VERSION 5.8 ;
BUSBITCHARS "[]" ;
DIVIDERCHAR "/" ;
UNITS
    DATABASE MICRONS 1000 ;
END UNITS

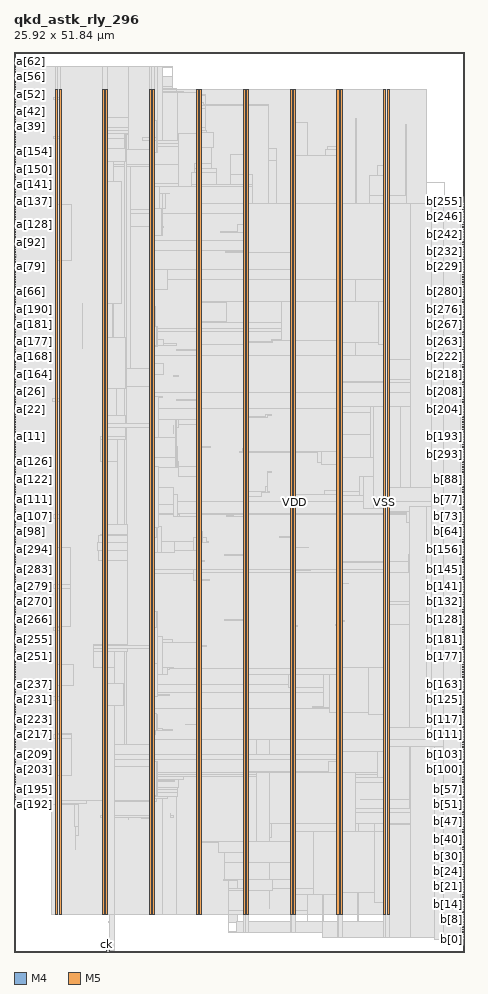
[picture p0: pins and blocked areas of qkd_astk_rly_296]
MACRO qkd_astk_rly_296
  FOREIGN qkd_astk_rly_296 0 0 ;
  CLASS BLOCK ;
  SIZE 25.92 BY 51.84 ;
  PIN a[0]
    DIRECTION INPUT ;
    USE SIGNAL ;
    PORT
      LAYER M4 ;
        RECT  0 28.08 0.084 28.104 ;
    END
  END a[0]
  PIN a[100]
    DIRECTION INPUT ;
    USE SIGNAL ;
    PORT
      LAYER M4 ;
        RECT  0 24.048 0.084 24.072 ;
    END
  END a[100]
  PIN a[101]
    DIRECTION INPUT ;
    USE SIGNAL ;
    PORT
      LAYER M4 ;
        RECT  0 24.192 0.084 24.216 ;
    END
  END a[101]
  PIN a[102]
    DIRECTION INPUT ;
    USE SIGNAL ;
    PORT
      LAYER M4 ;
        RECT  0 24.336 0.084 24.36 ;
    END
  END a[102]
  PIN a[103]
    DIRECTION INPUT ;
    USE SIGNAL ;
    PORT
      LAYER M4 ;
        RECT  0 24.48 0.084 24.504 ;
    END
  END a[103]
  PIN a[104]
    DIRECTION INPUT ;
    USE SIGNAL ;
    PORT
      LAYER M4 ;
        RECT  0 24.624 0.084 24.648 ;
    END
  END a[104]
  PIN a[105]
    DIRECTION INPUT ;
    USE SIGNAL ;
    PORT
      LAYER M4 ;
        RECT  0 24.768 0.084 24.792 ;
    END
  END a[105]
  PIN a[106]
    DIRECTION INPUT ;
    USE SIGNAL ;
    PORT
      LAYER M4 ;
        RECT  0 24.912 0.084 24.936 ;
    END
  END a[106]
  PIN a[107]
    DIRECTION INPUT ;
    USE SIGNAL ;
    PORT
      LAYER M4 ;
        RECT  0 25.056 0.084 25.08 ;
    END
  END a[107]
  PIN a[108]
    DIRECTION INPUT ;
    USE SIGNAL ;
    PORT
      LAYER M4 ;
        RECT  0 25.2 0.084 25.224 ;
    END
  END a[108]
  PIN a[109]
    DIRECTION INPUT ;
    USE SIGNAL ;
    PORT
      LAYER M4 ;
        RECT  0 25.344 0.084 25.368 ;
    END
  END a[109]
  PIN a[10]
    DIRECTION INPUT ;
    USE SIGNAL ;
    PORT
      LAYER M4 ;
        RECT  0 29.52 0.084 29.544 ;
    END
  END a[10]
  PIN a[110]
    DIRECTION INPUT ;
    USE SIGNAL ;
    PORT
      LAYER M4 ;
        RECT  0 25.488 0.084 25.512 ;
    END
  END a[110]
  PIN a[111]
    DIRECTION INPUT ;
    USE SIGNAL ;
    PORT
      LAYER M4 ;
        RECT  0 25.632 0.084 25.656 ;
    END
  END a[111]
  PIN a[112]
    DIRECTION INPUT ;
    USE SIGNAL ;
    PORT
      LAYER M4 ;
        RECT  0 25.776 0.084 25.8 ;
    END
  END a[112]
  PIN a[113]
    DIRECTION INPUT ;
    USE SIGNAL ;
    PORT
      LAYER M4 ;
        RECT  0 25.92 0.084 25.944 ;
    END
  END a[113]
  PIN a[114]
    DIRECTION INPUT ;
    USE SIGNAL ;
    PORT
      LAYER M4 ;
        RECT  0 26.064 0.084 26.088 ;
    END
  END a[114]
  PIN a[115]
    DIRECTION INPUT ;
    USE SIGNAL ;
    PORT
      LAYER M4 ;
        RECT  0 26.208 0.084 26.232 ;
    END
  END a[115]
  PIN a[116]
    DIRECTION INPUT ;
    USE SIGNAL ;
    PORT
      LAYER M4 ;
        RECT  0 26.352 0.084 26.376 ;
    END
  END a[116]
  PIN a[117]
    DIRECTION INPUT ;
    USE SIGNAL ;
    PORT
      LAYER M4 ;
        RECT  0 26.496 0.084 26.52 ;
    END
  END a[117]
  PIN a[118]
    DIRECTION INPUT ;
    USE SIGNAL ;
    PORT
      LAYER M4 ;
        RECT  0 26.64 0.084 26.664 ;
    END
  END a[118]
  PIN a[119]
    DIRECTION INPUT ;
    USE SIGNAL ;
    PORT
      LAYER M4 ;
        RECT  0 26.784 0.084 26.808 ;
    END
  END a[119]
  PIN a[11]
    DIRECTION INPUT ;
    USE SIGNAL ;
    PORT
      LAYER M4 ;
        RECT  0 29.664 0.084 29.688 ;
    END
  END a[11]
  PIN a[120]
    DIRECTION INPUT ;
    USE SIGNAL ;
    PORT
      LAYER M4 ;
        RECT  0 26.928 0.084 26.952 ;
    END
  END a[120]
  PIN a[121]
    DIRECTION INPUT ;
    USE SIGNAL ;
    PORT
      LAYER M4 ;
        RECT  0 27.072 0.084 27.096 ;
    END
  END a[121]
  PIN a[122]
    DIRECTION INPUT ;
    USE SIGNAL ;
    PORT
      LAYER M4 ;
        RECT  0 27.216 0.084 27.24 ;
    END
  END a[122]
  PIN a[123]
    DIRECTION INPUT ;
    USE SIGNAL ;
    PORT
      LAYER M4 ;
        RECT  0 27.36 0.084 27.384 ;
    END
  END a[123]
  PIN a[124]
    DIRECTION INPUT ;
    USE SIGNAL ;
    PORT
      LAYER M4 ;
        RECT  0 27.504 0.084 27.528 ;
    END
  END a[124]
  PIN a[125]
    DIRECTION INPUT ;
    USE SIGNAL ;
    PORT
      LAYER M4 ;
        RECT  0 27.648 0.084 27.672 ;
    END
  END a[125]
  PIN a[126]
    DIRECTION INPUT ;
    USE SIGNAL ;
    PORT
      LAYER M4 ;
        RECT  0 27.792 0.084 27.816 ;
    END
  END a[126]
  PIN a[127]
    DIRECTION INPUT ;
    USE SIGNAL ;
    PORT
      LAYER M4 ;
        RECT  0 27.936 0.084 27.96 ;
    END
  END a[127]
  PIN a[128]
    DIRECTION INPUT ;
    USE SIGNAL ;
    PORT
      LAYER M4 ;
        RECT  0 41.904 0.084 41.928 ;
    END
  END a[128]
  PIN a[129]
    DIRECTION INPUT ;
    USE SIGNAL ;
    PORT
      LAYER M4 ;
        RECT  0 42.048 0.084 42.072 ;
    END
  END a[129]
  PIN a[12]
    DIRECTION INPUT ;
    USE SIGNAL ;
    PORT
      LAYER M4 ;
        RECT  0 29.808 0.084 29.832 ;
    END
  END a[12]
  PIN a[130]
    DIRECTION INPUT ;
    USE SIGNAL ;
    PORT
      LAYER M4 ;
        RECT  0 42.192 0.084 42.216 ;
    END
  END a[130]
  PIN a[131]
    DIRECTION INPUT ;
    USE SIGNAL ;
    PORT
      LAYER M4 ;
        RECT  0 42.336 0.084 42.36 ;
    END
  END a[131]
  PIN a[132]
    DIRECTION INPUT ;
    USE SIGNAL ;
    PORT
      LAYER M4 ;
        RECT  0 42.48 0.084 42.504 ;
    END
  END a[132]
  PIN a[133]
    DIRECTION INPUT ;
    USE SIGNAL ;
    PORT
      LAYER M4 ;
        RECT  0 42.624 0.084 42.648 ;
    END
  END a[133]
  PIN a[134]
    DIRECTION INPUT ;
    USE SIGNAL ;
    PORT
      LAYER M4 ;
        RECT  0 42.768 0.084 42.792 ;
    END
  END a[134]
  PIN a[135]
    DIRECTION INPUT ;
    USE SIGNAL ;
    PORT
      LAYER M4 ;
        RECT  0 42.912 0.084 42.936 ;
    END
  END a[135]
  PIN a[136]
    DIRECTION INPUT ;
    USE SIGNAL ;
    PORT
      LAYER M4 ;
        RECT  0 43.056 0.084 43.08 ;
    END
  END a[136]
  PIN a[137]
    DIRECTION INPUT ;
    USE SIGNAL ;
    PORT
      LAYER M4 ;
        RECT  0 43.2 0.084 43.224 ;
    END
  END a[137]
  PIN a[138]
    DIRECTION INPUT ;
    USE SIGNAL ;
    PORT
      LAYER M4 ;
        RECT  0 43.344 0.084 43.368 ;
    END
  END a[138]
  PIN a[139]
    DIRECTION INPUT ;
    USE SIGNAL ;
    PORT
      LAYER M4 ;
        RECT  0 43.488 0.084 43.512 ;
    END
  END a[139]
  PIN a[13]
    DIRECTION INPUT ;
    USE SIGNAL ;
    PORT
      LAYER M4 ;
        RECT  0 29.952 0.084 29.976 ;
    END
  END a[13]
  PIN a[140]
    DIRECTION INPUT ;
    USE SIGNAL ;
    PORT
      LAYER M4 ;
        RECT  0 43.632 0.084 43.656 ;
    END
  END a[140]
  PIN a[141]
    DIRECTION INPUT ;
    USE SIGNAL ;
    PORT
      LAYER M4 ;
        RECT  0 43.776 0.084 43.8 ;
    END
  END a[141]
  PIN a[142]
    DIRECTION INPUT ;
    USE SIGNAL ;
    PORT
      LAYER M4 ;
        RECT  0 43.92 0.084 43.944 ;
    END
  END a[142]
  PIN a[143]
    DIRECTION INPUT ;
    USE SIGNAL ;
    PORT
      LAYER M4 ;
        RECT  0 44.064 0.084 44.088 ;
    END
  END a[143]
  PIN a[144]
    DIRECTION INPUT ;
    USE SIGNAL ;
    PORT
      LAYER M4 ;
        RECT  0 44.208 0.084 44.232 ;
    END
  END a[144]
  PIN a[145]
    DIRECTION INPUT ;
    USE SIGNAL ;
    PORT
      LAYER M4 ;
        RECT  0 44.352 0.084 44.376 ;
    END
  END a[145]
  PIN a[146]
    DIRECTION INPUT ;
    USE SIGNAL ;
    PORT
      LAYER M4 ;
        RECT  0 44.496 0.084 44.52 ;
    END
  END a[146]
  PIN a[147]
    DIRECTION INPUT ;
    USE SIGNAL ;
    PORT
      LAYER M4 ;
        RECT  0 44.64 0.084 44.664 ;
    END
  END a[147]
  PIN a[148]
    DIRECTION INPUT ;
    USE SIGNAL ;
    PORT
      LAYER M4 ;
        RECT  0 44.784 0.084 44.808 ;
    END
  END a[148]
  PIN a[149]
    DIRECTION INPUT ;
    USE SIGNAL ;
    PORT
      LAYER M4 ;
        RECT  0 44.928 0.084 44.952 ;
    END
  END a[149]
  PIN a[14]
    DIRECTION INPUT ;
    USE SIGNAL ;
    PORT
      LAYER M4 ;
        RECT  0 30.096 0.084 30.12 ;
    END
  END a[14]
  PIN a[150]
    DIRECTION INPUT ;
    USE SIGNAL ;
    PORT
      LAYER M4 ;
        RECT  0 45.072 0.084 45.096 ;
    END
  END a[150]
  PIN a[151]
    DIRECTION INPUT ;
    USE SIGNAL ;
    PORT
      LAYER M4 ;
        RECT  0 45.216 0.084 45.24 ;
    END
  END a[151]
  PIN a[152]
    DIRECTION INPUT ;
    USE SIGNAL ;
    PORT
      LAYER M4 ;
        RECT  0 45.36 0.084 45.384 ;
    END
  END a[152]
  PIN a[153]
    DIRECTION INPUT ;
    USE SIGNAL ;
    PORT
      LAYER M4 ;
        RECT  0 45.504 0.084 45.528 ;
    END
  END a[153]
  PIN a[154]
    DIRECTION INPUT ;
    USE SIGNAL ;
    PORT
      LAYER M4 ;
        RECT  0 45.648 0.084 45.672 ;
    END
  END a[154]
  PIN a[155]
    DIRECTION INPUT ;
    USE SIGNAL ;
    PORT
      LAYER M4 ;
        RECT  0 45.792 0.084 45.816 ;
    END
  END a[155]
  PIN a[156]
    DIRECTION INPUT ;
    USE SIGNAL ;
    PORT
      LAYER M4 ;
        RECT  0 45.936 0.084 45.96 ;
    END
  END a[156]
  PIN a[157]
    DIRECTION INPUT ;
    USE SIGNAL ;
    PORT
      LAYER M4 ;
        RECT  0 46.08 0.084 46.104 ;
    END
  END a[157]
  PIN a[158]
    DIRECTION INPUT ;
    USE SIGNAL ;
    PORT
      LAYER M4 ;
        RECT  0 46.224 0.084 46.248 ;
    END
  END a[158]
  PIN a[159]
    DIRECTION INPUT ;
    USE SIGNAL ;
    PORT
      LAYER M4 ;
        RECT  0 46.368 0.084 46.392 ;
    END
  END a[159]
  PIN a[15]
    DIRECTION INPUT ;
    USE SIGNAL ;
    PORT
      LAYER M4 ;
        RECT  0 30.24 0.084 30.264 ;
    END
  END a[15]
  PIN a[160]
    DIRECTION INPUT ;
    USE SIGNAL ;
    PORT
      LAYER M4 ;
        RECT  0 32.688 0.084 32.712 ;
    END
  END a[160]
  PIN a[161]
    DIRECTION INPUT ;
    USE SIGNAL ;
    PORT
      LAYER M4 ;
        RECT  0 32.832 0.084 32.856 ;
    END
  END a[161]
  PIN a[162]
    DIRECTION INPUT ;
    USE SIGNAL ;
    PORT
      LAYER M4 ;
        RECT  0 32.976 0.084 33 ;
    END
  END a[162]
  PIN a[163]
    DIRECTION INPUT ;
    USE SIGNAL ;
    PORT
      LAYER M4 ;
        RECT  0 33.12 0.084 33.144 ;
    END
  END a[163]
  PIN a[164]
    DIRECTION INPUT ;
    USE SIGNAL ;
    PORT
      LAYER M4 ;
        RECT  0 33.264 0.084 33.288 ;
    END
  END a[164]
  PIN a[165]
    DIRECTION INPUT ;
    USE SIGNAL ;
    PORT
      LAYER M4 ;
        RECT  0 33.408 0.084 33.432 ;
    END
  END a[165]
  PIN a[166]
    DIRECTION INPUT ;
    USE SIGNAL ;
    PORT
      LAYER M4 ;
        RECT  0 33.552 0.084 33.576 ;
    END
  END a[166]
  PIN a[167]
    DIRECTION INPUT ;
    USE SIGNAL ;
    PORT
      LAYER M4 ;
        RECT  0 33.696 0.084 33.72 ;
    END
  END a[167]
  PIN a[168]
    DIRECTION INPUT ;
    USE SIGNAL ;
    PORT
      LAYER M4 ;
        RECT  0 33.84 0.084 33.864 ;
    END
  END a[168]
  PIN a[169]
    DIRECTION INPUT ;
    USE SIGNAL ;
    PORT
      LAYER M4 ;
        RECT  0 33.984 0.084 34.008 ;
    END
  END a[169]
  PIN a[16]
    DIRECTION INPUT ;
    USE SIGNAL ;
    PORT
      LAYER M4 ;
        RECT  0 30.384 0.084 30.408 ;
    END
  END a[16]
  PIN a[170]
    DIRECTION INPUT ;
    USE SIGNAL ;
    PORT
      LAYER M4 ;
        RECT  0 34.128 0.084 34.152 ;
    END
  END a[170]
  PIN a[171]
    DIRECTION INPUT ;
    USE SIGNAL ;
    PORT
      LAYER M4 ;
        RECT  0 34.272 0.084 34.296 ;
    END
  END a[171]
  PIN a[172]
    DIRECTION INPUT ;
    USE SIGNAL ;
    PORT
      LAYER M4 ;
        RECT  0 34.416 0.084 34.44 ;
    END
  END a[172]
  PIN a[173]
    DIRECTION INPUT ;
    USE SIGNAL ;
    PORT
      LAYER M4 ;
        RECT  0 34.56 0.084 34.584 ;
    END
  END a[173]
  PIN a[174]
    DIRECTION INPUT ;
    USE SIGNAL ;
    PORT
      LAYER M4 ;
        RECT  0 34.704 0.084 34.728 ;
    END
  END a[174]
  PIN a[175]
    DIRECTION INPUT ;
    USE SIGNAL ;
    PORT
      LAYER M4 ;
        RECT  0 34.848 0.084 34.872 ;
    END
  END a[175]
  PIN a[176]
    DIRECTION INPUT ;
    USE SIGNAL ;
    PORT
      LAYER M4 ;
        RECT  0 34.992 0.084 35.016 ;
    END
  END a[176]
  PIN a[177]
    DIRECTION INPUT ;
    USE SIGNAL ;
    PORT
      LAYER M4 ;
        RECT  0 35.136 0.084 35.16 ;
    END
  END a[177]
  PIN a[178]
    DIRECTION INPUT ;
    USE SIGNAL ;
    PORT
      LAYER M4 ;
        RECT  0 35.28 0.084 35.304 ;
    END
  END a[178]
  PIN a[179]
    DIRECTION INPUT ;
    USE SIGNAL ;
    PORT
      LAYER M4 ;
        RECT  0 35.424 0.084 35.448 ;
    END
  END a[179]
  PIN a[17]
    DIRECTION INPUT ;
    USE SIGNAL ;
    PORT
      LAYER M4 ;
        RECT  0 30.528 0.084 30.552 ;
    END
  END a[17]
  PIN a[180]
    DIRECTION INPUT ;
    USE SIGNAL ;
    PORT
      LAYER M4 ;
        RECT  0 35.568 0.084 35.592 ;
    END
  END a[180]
  PIN a[181]
    DIRECTION INPUT ;
    USE SIGNAL ;
    PORT
      LAYER M4 ;
        RECT  0 35.712 0.084 35.736 ;
    END
  END a[181]
  PIN a[182]
    DIRECTION INPUT ;
    USE SIGNAL ;
    PORT
      LAYER M4 ;
        RECT  0 35.856 0.084 35.88 ;
    END
  END a[182]
  PIN a[183]
    DIRECTION INPUT ;
    USE SIGNAL ;
    PORT
      LAYER M4 ;
        RECT  0 36 0.084 36.024 ;
    END
  END a[183]
  PIN a[184]
    DIRECTION INPUT ;
    USE SIGNAL ;
    PORT
      LAYER M4 ;
        RECT  0 36.144 0.084 36.168 ;
    END
  END a[184]
  PIN a[185]
    DIRECTION INPUT ;
    USE SIGNAL ;
    PORT
      LAYER M4 ;
        RECT  0 36.288 0.084 36.312 ;
    END
  END a[185]
  PIN a[186]
    DIRECTION INPUT ;
    USE SIGNAL ;
    PORT
      LAYER M4 ;
        RECT  0 36.432 0.084 36.456 ;
    END
  END a[186]
  PIN a[187]
    DIRECTION INPUT ;
    USE SIGNAL ;
    PORT
      LAYER M4 ;
        RECT  0 36.576 0.084 36.6 ;
    END
  END a[187]
  PIN a[188]
    DIRECTION INPUT ;
    USE SIGNAL ;
    PORT
      LAYER M4 ;
        RECT  0 36.72 0.084 36.744 ;
    END
  END a[188]
  PIN a[189]
    DIRECTION INPUT ;
    USE SIGNAL ;
    PORT
      LAYER M4 ;
        RECT  0 36.864 0.084 36.888 ;
    END
  END a[189]
  PIN a[18]
    DIRECTION INPUT ;
    USE SIGNAL ;
    PORT
      LAYER M4 ;
        RECT  0 30.672 0.084 30.696 ;
    END
  END a[18]
  PIN a[190]
    DIRECTION INPUT ;
    USE SIGNAL ;
    PORT
      LAYER M4 ;
        RECT  0 37.008 0.084 37.032 ;
    END
  END a[190]
  PIN a[191]
    DIRECTION INPUT ;
    USE SIGNAL ;
    PORT
      LAYER M4 ;
        RECT  0 37.152 0.084 37.176 ;
    END
  END a[191]
  PIN a[192]
    DIRECTION INPUT ;
    USE SIGNAL ;
    PORT
      LAYER M4 ;
        RECT  0 8.496 0.084 8.52 ;
    END
  END a[192]
  PIN a[193]
    DIRECTION INPUT ;
    USE SIGNAL ;
    PORT
      LAYER M4 ;
        RECT  0 8.64 0.084 8.664 ;
    END
  END a[193]
  PIN a[194]
    DIRECTION INPUT ;
    USE SIGNAL ;
    PORT
      LAYER M4 ;
        RECT  0 8.784 0.084 8.808 ;
    END
  END a[194]
  PIN a[195]
    DIRECTION INPUT ;
    USE SIGNAL ;
    PORT
      LAYER M4 ;
        RECT  0 8.928 0.084 8.952 ;
    END
  END a[195]
  PIN a[196]
    DIRECTION INPUT ;
    USE SIGNAL ;
    PORT
      LAYER M4 ;
        RECT  0 9.072 0.084 9.096 ;
    END
  END a[196]
  PIN a[197]
    DIRECTION INPUT ;
    USE SIGNAL ;
    PORT
      LAYER M4 ;
        RECT  0 9.216 0.084 9.24 ;
    END
  END a[197]
  PIN a[198]
    DIRECTION INPUT ;
    USE SIGNAL ;
    PORT
      LAYER M4 ;
        RECT  0 9.36 0.084 9.384 ;
    END
  END a[198]
  PIN a[199]
    DIRECTION INPUT ;
    USE SIGNAL ;
    PORT
      LAYER M4 ;
        RECT  0 9.504 0.084 9.528 ;
    END
  END a[199]
  PIN a[19]
    DIRECTION INPUT ;
    USE SIGNAL ;
    PORT
      LAYER M4 ;
        RECT  0 30.816 0.084 30.84 ;
    END
  END a[19]
  PIN a[1]
    DIRECTION INPUT ;
    USE SIGNAL ;
    PORT
      LAYER M4 ;
        RECT  0 28.224 0.084 28.248 ;
    END
  END a[1]
  PIN a[200]
    DIRECTION INPUT ;
    USE SIGNAL ;
    PORT
      LAYER M4 ;
        RECT  0 9.648 0.084 9.672 ;
    END
  END a[200]
  PIN a[201]
    DIRECTION INPUT ;
    USE SIGNAL ;
    PORT
      LAYER M4 ;
        RECT  0 9.792 0.084 9.816 ;
    END
  END a[201]
  PIN a[202]
    DIRECTION INPUT ;
    USE SIGNAL ;
    PORT
      LAYER M4 ;
        RECT  0 9.936 0.084 9.96 ;
    END
  END a[202]
  PIN a[203]
    DIRECTION INPUT ;
    USE SIGNAL ;
    PORT
      LAYER M4 ;
        RECT  0 10.08 0.084 10.104 ;
    END
  END a[203]
  PIN a[204]
    DIRECTION INPUT ;
    USE SIGNAL ;
    PORT
      LAYER M4 ;
        RECT  0 10.224 0.084 10.248 ;
    END
  END a[204]
  PIN a[205]
    DIRECTION INPUT ;
    USE SIGNAL ;
    PORT
      LAYER M4 ;
        RECT  0 10.368 0.084 10.392 ;
    END
  END a[205]
  PIN a[206]
    DIRECTION INPUT ;
    USE SIGNAL ;
    PORT
      LAYER M4 ;
        RECT  0 10.512 0.084 10.536 ;
    END
  END a[206]
  PIN a[207]
    DIRECTION INPUT ;
    USE SIGNAL ;
    PORT
      LAYER M4 ;
        RECT  0 10.656 0.084 10.68 ;
    END
  END a[207]
  PIN a[208]
    DIRECTION INPUT ;
    USE SIGNAL ;
    PORT
      LAYER M4 ;
        RECT  0 10.8 0.084 10.824 ;
    END
  END a[208]
  PIN a[209]
    DIRECTION INPUT ;
    USE SIGNAL ;
    PORT
      LAYER M4 ;
        RECT  0 10.944 0.084 10.968 ;
    END
  END a[209]
  PIN a[20]
    DIRECTION INPUT ;
    USE SIGNAL ;
    PORT
      LAYER M4 ;
        RECT  0 30.96 0.084 30.984 ;
    END
  END a[20]
  PIN a[210]
    DIRECTION INPUT ;
    USE SIGNAL ;
    PORT
      LAYER M4 ;
        RECT  0 11.088 0.084 11.112 ;
    END
  END a[210]
  PIN a[211]
    DIRECTION INPUT ;
    USE SIGNAL ;
    PORT
      LAYER M4 ;
        RECT  0 11.232 0.084 11.256 ;
    END
  END a[211]
  PIN a[212]
    DIRECTION INPUT ;
    USE SIGNAL ;
    PORT
      LAYER M4 ;
        RECT  0 11.376 0.084 11.4 ;
    END
  END a[212]
  PIN a[213]
    DIRECTION INPUT ;
    USE SIGNAL ;
    PORT
      LAYER M4 ;
        RECT  0 11.52 0.084 11.544 ;
    END
  END a[213]
  PIN a[214]
    DIRECTION INPUT ;
    USE SIGNAL ;
    PORT
      LAYER M4 ;
        RECT  0 11.664 0.084 11.688 ;
    END
  END a[214]
  PIN a[215]
    DIRECTION INPUT ;
    USE SIGNAL ;
    PORT
      LAYER M4 ;
        RECT  0 11.808 0.084 11.832 ;
    END
  END a[215]
  PIN a[216]
    DIRECTION INPUT ;
    USE SIGNAL ;
    PORT
      LAYER M4 ;
        RECT  0 11.952 0.084 11.976 ;
    END
  END a[216]
  PIN a[217]
    DIRECTION INPUT ;
    USE SIGNAL ;
    PORT
      LAYER M4 ;
        RECT  0 12.096 0.084 12.12 ;
    END
  END a[217]
  PIN a[218]
    DIRECTION INPUT ;
    USE SIGNAL ;
    PORT
      LAYER M4 ;
        RECT  0 12.24 0.084 12.264 ;
    END
  END a[218]
  PIN a[219]
    DIRECTION INPUT ;
    USE SIGNAL ;
    PORT
      LAYER M4 ;
        RECT  0 12.384 0.084 12.408 ;
    END
  END a[219]
  PIN a[21]
    DIRECTION INPUT ;
    USE SIGNAL ;
    PORT
      LAYER M4 ;
        RECT  0 31.104 0.084 31.128 ;
    END
  END a[21]
  PIN a[220]
    DIRECTION INPUT ;
    USE SIGNAL ;
    PORT
      LAYER M4 ;
        RECT  0 12.528 0.084 12.552 ;
    END
  END a[220]
  PIN a[221]
    DIRECTION INPUT ;
    USE SIGNAL ;
    PORT
      LAYER M4 ;
        RECT  0 12.672 0.084 12.696 ;
    END
  END a[221]
  PIN a[222]
    DIRECTION INPUT ;
    USE SIGNAL ;
    PORT
      LAYER M4 ;
        RECT  0 12.816 0.084 12.84 ;
    END
  END a[222]
  PIN a[223]
    DIRECTION INPUT ;
    USE SIGNAL ;
    PORT
      LAYER M4 ;
        RECT  0 12.96 0.084 12.984 ;
    END
  END a[223]
  PIN a[224]
    DIRECTION INPUT ;
    USE SIGNAL ;
    PORT
      LAYER M4 ;
        RECT  0 13.104 0.084 13.128 ;
    END
  END a[224]
  PIN a[225]
    DIRECTION INPUT ;
    USE SIGNAL ;
    PORT
      LAYER M4 ;
        RECT  0 13.248 0.084 13.272 ;
    END
  END a[225]
  PIN a[226]
    DIRECTION INPUT ;
    USE SIGNAL ;
    PORT
      LAYER M4 ;
        RECT  0 13.392 0.084 13.416 ;
    END
  END a[226]
  PIN a[227]
    DIRECTION INPUT ;
    USE SIGNAL ;
    PORT
      LAYER M4 ;
        RECT  0 13.536 0.084 13.56 ;
    END
  END a[227]
  PIN a[228]
    DIRECTION INPUT ;
    USE SIGNAL ;
    PORT
      LAYER M4 ;
        RECT  0 13.68 0.084 13.704 ;
    END
  END a[228]
  PIN a[229]
    DIRECTION INPUT ;
    USE SIGNAL ;
    PORT
      LAYER M4 ;
        RECT  0 13.824 0.084 13.848 ;
    END
  END a[229]
  PIN a[22]
    DIRECTION INPUT ;
    USE SIGNAL ;
    PORT
      LAYER M4 ;
        RECT  0 31.248 0.084 31.272 ;
    END
  END a[22]
  PIN a[230]
    DIRECTION INPUT ;
    USE SIGNAL ;
    PORT
      LAYER M4 ;
        RECT  0 13.968 0.084 13.992 ;
    END
  END a[230]
  PIN a[231]
    DIRECTION INPUT ;
    USE SIGNAL ;
    PORT
      LAYER M4 ;
        RECT  0 14.112 0.084 14.136 ;
    END
  END a[231]
  PIN a[232]
    DIRECTION INPUT ;
    USE SIGNAL ;
    PORT
      LAYER M4 ;
        RECT  0 14.256 0.084 14.28 ;
    END
  END a[232]
  PIN a[233]
    DIRECTION INPUT ;
    USE SIGNAL ;
    PORT
      LAYER M4 ;
        RECT  0 14.4 0.084 14.424 ;
    END
  END a[233]
  PIN a[234]
    DIRECTION INPUT ;
    USE SIGNAL ;
    PORT
      LAYER M4 ;
        RECT  0 14.544 0.084 14.568 ;
    END
  END a[234]
  PIN a[235]
    DIRECTION INPUT ;
    USE SIGNAL ;
    PORT
      LAYER M4 ;
        RECT  0 14.688 0.084 14.712 ;
    END
  END a[235]
  PIN a[236]
    DIRECTION INPUT ;
    USE SIGNAL ;
    PORT
      LAYER M4 ;
        RECT  0 14.832 0.084 14.856 ;
    END
  END a[236]
  PIN a[237]
    DIRECTION INPUT ;
    USE SIGNAL ;
    PORT
      LAYER M4 ;
        RECT  0 14.976 0.084 15 ;
    END
  END a[237]
  PIN a[238]
    DIRECTION INPUT ;
    USE SIGNAL ;
    PORT
      LAYER M4 ;
        RECT  0 15.12 0.084 15.144 ;
    END
  END a[238]
  PIN a[239]
    DIRECTION INPUT ;
    USE SIGNAL ;
    PORT
      LAYER M4 ;
        RECT  0 15.264 0.084 15.288 ;
    END
  END a[239]
  PIN a[23]
    DIRECTION INPUT ;
    USE SIGNAL ;
    PORT
      LAYER M4 ;
        RECT  0 31.392 0.084 31.416 ;
    END
  END a[23]
  PIN a[240]
    DIRECTION INPUT ;
    USE SIGNAL ;
    PORT
      LAYER M4 ;
        RECT  0 15.408 0.084 15.432 ;
    END
  END a[240]
  PIN a[241]
    DIRECTION INPUT ;
    USE SIGNAL ;
    PORT
      LAYER M4 ;
        RECT  0 15.552 0.084 15.576 ;
    END
  END a[241]
  PIN a[242]
    DIRECTION INPUT ;
    USE SIGNAL ;
    PORT
      LAYER M4 ;
        RECT  0 15.696 0.084 15.72 ;
    END
  END a[242]
  PIN a[243]
    DIRECTION INPUT ;
    USE SIGNAL ;
    PORT
      LAYER M4 ;
        RECT  0 15.84 0.084 15.864 ;
    END
  END a[243]
  PIN a[244]
    DIRECTION INPUT ;
    USE SIGNAL ;
    PORT
      LAYER M4 ;
        RECT  0 15.984 0.084 16.008 ;
    END
  END a[244]
  PIN a[245]
    DIRECTION INPUT ;
    USE SIGNAL ;
    PORT
      LAYER M4 ;
        RECT  0 16.128 0.084 16.152 ;
    END
  END a[245]
  PIN a[246]
    DIRECTION INPUT ;
    USE SIGNAL ;
    PORT
      LAYER M4 ;
        RECT  0 16.272 0.084 16.296 ;
    END
  END a[246]
  PIN a[247]
    DIRECTION INPUT ;
    USE SIGNAL ;
    PORT
      LAYER M4 ;
        RECT  0 16.416 0.084 16.44 ;
    END
  END a[247]
  PIN a[248]
    DIRECTION INPUT ;
    USE SIGNAL ;
    PORT
      LAYER M4 ;
        RECT  0 16.56 0.084 16.584 ;
    END
  END a[248]
  PIN a[249]
    DIRECTION INPUT ;
    USE SIGNAL ;
    PORT
      LAYER M4 ;
        RECT  0 16.704 0.084 16.728 ;
    END
  END a[249]
  PIN a[24]
    DIRECTION INPUT ;
    USE SIGNAL ;
    PORT
      LAYER M4 ;
        RECT  0 31.536 0.084 31.56 ;
    END
  END a[24]
  PIN a[250]
    DIRECTION INPUT ;
    USE SIGNAL ;
    PORT
      LAYER M4 ;
        RECT  0 16.848 0.084 16.872 ;
    END
  END a[250]
  PIN a[251]
    DIRECTION INPUT ;
    USE SIGNAL ;
    PORT
      LAYER M4 ;
        RECT  0 16.992 0.084 17.016 ;
    END
  END a[251]
  PIN a[252]
    DIRECTION INPUT ;
    USE SIGNAL ;
    PORT
      LAYER M4 ;
        RECT  0 17.136 0.084 17.16 ;
    END
  END a[252]
  PIN a[253]
    DIRECTION INPUT ;
    USE SIGNAL ;
    PORT
      LAYER M4 ;
        RECT  0 17.28 0.084 17.304 ;
    END
  END a[253]
  PIN a[254]
    DIRECTION INPUT ;
    USE SIGNAL ;
    PORT
      LAYER M4 ;
        RECT  0 17.424 0.084 17.448 ;
    END
  END a[254]
  PIN a[255]
    DIRECTION INPUT ;
    USE SIGNAL ;
    PORT
      LAYER M4 ;
        RECT  0 17.568 0.084 17.592 ;
    END
  END a[255]
  PIN a[256]
    DIRECTION INPUT ;
    USE SIGNAL ;
    PORT
      LAYER M4 ;
        RECT  0 17.712 0.084 17.736 ;
    END
  END a[256]
  PIN a[257]
    DIRECTION INPUT ;
    USE SIGNAL ;
    PORT
      LAYER M4 ;
        RECT  0 17.856 0.084 17.88 ;
    END
  END a[257]
  PIN a[258]
    DIRECTION INPUT ;
    USE SIGNAL ;
    PORT
      LAYER M4 ;
        RECT  0 18 0.084 18.024 ;
    END
  END a[258]
  PIN a[259]
    DIRECTION INPUT ;
    USE SIGNAL ;
    PORT
      LAYER M4 ;
        RECT  0 18.144 0.084 18.168 ;
    END
  END a[259]
  PIN a[25]
    DIRECTION INPUT ;
    USE SIGNAL ;
    PORT
      LAYER M4 ;
        RECT  0 31.68 0.084 31.704 ;
    END
  END a[25]
  PIN a[260]
    DIRECTION INPUT ;
    USE SIGNAL ;
    PORT
      LAYER M4 ;
        RECT  0 18.288 0.084 18.312 ;
    END
  END a[260]
  PIN a[261]
    DIRECTION INPUT ;
    USE SIGNAL ;
    PORT
      LAYER M4 ;
        RECT  0 18.432 0.084 18.456 ;
    END
  END a[261]
  PIN a[262]
    DIRECTION INPUT ;
    USE SIGNAL ;
    PORT
      LAYER M4 ;
        RECT  0 18.576 0.084 18.6 ;
    END
  END a[262]
  PIN a[263]
    DIRECTION INPUT ;
    USE SIGNAL ;
    PORT
      LAYER M4 ;
        RECT  0 18.72 0.084 18.744 ;
    END
  END a[263]
  PIN a[264]
    DIRECTION INPUT ;
    USE SIGNAL ;
    PORT
      LAYER M4 ;
        RECT  0 18.864 0.084 18.888 ;
    END
  END a[264]
  PIN a[265]
    DIRECTION INPUT ;
    USE SIGNAL ;
    PORT
      LAYER M4 ;
        RECT  0 19.008 0.084 19.032 ;
    END
  END a[265]
  PIN a[266]
    DIRECTION INPUT ;
    USE SIGNAL ;
    PORT
      LAYER M4 ;
        RECT  0 19.152 0.084 19.176 ;
    END
  END a[266]
  PIN a[267]
    DIRECTION INPUT ;
    USE SIGNAL ;
    PORT
      LAYER M4 ;
        RECT  0 19.296 0.084 19.32 ;
    END
  END a[267]
  PIN a[268]
    DIRECTION INPUT ;
    USE SIGNAL ;
    PORT
      LAYER M4 ;
        RECT  0 19.44 0.084 19.464 ;
    END
  END a[268]
  PIN a[269]
    DIRECTION INPUT ;
    USE SIGNAL ;
    PORT
      LAYER M4 ;
        RECT  0 19.584 0.084 19.608 ;
    END
  END a[269]
  PIN a[26]
    DIRECTION INPUT ;
    USE SIGNAL ;
    PORT
      LAYER M4 ;
        RECT  0 31.824 0.084 31.848 ;
    END
  END a[26]
  PIN a[270]
    DIRECTION INPUT ;
    USE SIGNAL ;
    PORT
      LAYER M4 ;
        RECT  0 19.728 0.084 19.752 ;
    END
  END a[270]
  PIN a[271]
    DIRECTION INPUT ;
    USE SIGNAL ;
    PORT
      LAYER M4 ;
        RECT  0 19.872 0.084 19.896 ;
    END
  END a[271]
  PIN a[272]
    DIRECTION INPUT ;
    USE SIGNAL ;
    PORT
      LAYER M4 ;
        RECT  0 20.016 0.084 20.04 ;
    END
  END a[272]
  PIN a[273]
    DIRECTION INPUT ;
    USE SIGNAL ;
    PORT
      LAYER M4 ;
        RECT  0 20.16 0.084 20.184 ;
    END
  END a[273]
  PIN a[274]
    DIRECTION INPUT ;
    USE SIGNAL ;
    PORT
      LAYER M4 ;
        RECT  0 20.304 0.084 20.328 ;
    END
  END a[274]
  PIN a[275]
    DIRECTION INPUT ;
    USE SIGNAL ;
    PORT
      LAYER M4 ;
        RECT  0 20.448 0.084 20.472 ;
    END
  END a[275]
  PIN a[276]
    DIRECTION INPUT ;
    USE SIGNAL ;
    PORT
      LAYER M4 ;
        RECT  0 20.592 0.084 20.616 ;
    END
  END a[276]
  PIN a[277]
    DIRECTION INPUT ;
    USE SIGNAL ;
    PORT
      LAYER M4 ;
        RECT  0 20.736 0.084 20.76 ;
    END
  END a[277]
  PIN a[278]
    DIRECTION INPUT ;
    USE SIGNAL ;
    PORT
      LAYER M4 ;
        RECT  0 20.88 0.084 20.904 ;
    END
  END a[278]
  PIN a[279]
    DIRECTION INPUT ;
    USE SIGNAL ;
    PORT
      LAYER M4 ;
        RECT  0 21.024 0.084 21.048 ;
    END
  END a[279]
  PIN a[27]
    DIRECTION INPUT ;
    USE SIGNAL ;
    PORT
      LAYER M4 ;
        RECT  0 31.968 0.084 31.992 ;
    END
  END a[27]
  PIN a[280]
    DIRECTION INPUT ;
    USE SIGNAL ;
    PORT
      LAYER M4 ;
        RECT  0 21.168 0.084 21.192 ;
    END
  END a[280]
  PIN a[281]
    DIRECTION INPUT ;
    USE SIGNAL ;
    PORT
      LAYER M4 ;
        RECT  0 21.312 0.084 21.336 ;
    END
  END a[281]
  PIN a[282]
    DIRECTION INPUT ;
    USE SIGNAL ;
    PORT
      LAYER M4 ;
        RECT  0 21.456 0.084 21.48 ;
    END
  END a[282]
  PIN a[283]
    DIRECTION INPUT ;
    USE SIGNAL ;
    PORT
      LAYER M4 ;
        RECT  0 21.6 0.084 21.624 ;
    END
  END a[283]
  PIN a[284]
    DIRECTION INPUT ;
    USE SIGNAL ;
    PORT
      LAYER M4 ;
        RECT  0 21.744 0.084 21.768 ;
    END
  END a[284]
  PIN a[285]
    DIRECTION INPUT ;
    USE SIGNAL ;
    PORT
      LAYER M4 ;
        RECT  0 21.888 0.084 21.912 ;
    END
  END a[285]
  PIN a[286]
    DIRECTION INPUT ;
    USE SIGNAL ;
    PORT
      LAYER M4 ;
        RECT  0 22.032 0.084 22.056 ;
    END
  END a[286]
  PIN a[287]
    DIRECTION INPUT ;
    USE SIGNAL ;
    PORT
      LAYER M4 ;
        RECT  0 22.176 0.084 22.2 ;
    END
  END a[287]
  PIN a[288]
    DIRECTION INPUT ;
    USE SIGNAL ;
    PORT
      LAYER M4 ;
        RECT  0 22.32 0.084 22.344 ;
    END
  END a[288]
  PIN a[289]
    DIRECTION INPUT ;
    USE SIGNAL ;
    PORT
      LAYER M4 ;
        RECT  0 22.464 0.084 22.488 ;
    END
  END a[289]
  PIN a[28]
    DIRECTION INPUT ;
    USE SIGNAL ;
    PORT
      LAYER M4 ;
        RECT  0 32.112 0.084 32.136 ;
    END
  END a[28]
  PIN a[290]
    DIRECTION INPUT ;
    USE SIGNAL ;
    PORT
      LAYER M4 ;
        RECT  0 22.608 0.084 22.632 ;
    END
  END a[290]
  PIN a[291]
    DIRECTION INPUT ;
    USE SIGNAL ;
    PORT
      LAYER M4 ;
        RECT  0 22.752 0.084 22.776 ;
    END
  END a[291]
  PIN a[292]
    DIRECTION INPUT ;
    USE SIGNAL ;
    PORT
      LAYER M4 ;
        RECT  0 22.896 0.084 22.92 ;
    END
  END a[292]
  PIN a[293]
    DIRECTION INPUT ;
    USE SIGNAL ;
    PORT
      LAYER M4 ;
        RECT  0 23.04 0.084 23.064 ;
    END
  END a[293]
  PIN a[294]
    DIRECTION INPUT ;
    USE SIGNAL ;
    PORT
      LAYER M4 ;
        RECT  0 23.184 0.084 23.208 ;
    END
  END a[294]
  PIN a[295]
    DIRECTION INPUT ;
    USE SIGNAL ;
    PORT
      LAYER M4 ;
        RECT  0 23.328 0.084 23.352 ;
    END
  END a[295]
  PIN a[29]
    DIRECTION INPUT ;
    USE SIGNAL ;
    PORT
      LAYER M4 ;
        RECT  0 32.256 0.084 32.28 ;
    END
  END a[29]
  PIN a[2]
    DIRECTION INPUT ;
    USE SIGNAL ;
    PORT
      LAYER M4 ;
        RECT  0 28.368 0.084 28.392 ;
    END
  END a[2]
  PIN a[30]
    DIRECTION INPUT ;
    USE SIGNAL ;
    PORT
      LAYER M4 ;
        RECT  0 32.4 0.084 32.424 ;
    END
  END a[30]
  PIN a[31]
    DIRECTION INPUT ;
    USE SIGNAL ;
    PORT
      LAYER M4 ;
        RECT  0 32.544 0.084 32.568 ;
    END
  END a[31]
  PIN a[32]
    DIRECTION INPUT ;
    USE SIGNAL ;
    PORT
      LAYER M4 ;
        RECT  0 46.512 0.084 46.536 ;
    END
  END a[32]
  PIN a[33]
    DIRECTION INPUT ;
    USE SIGNAL ;
    PORT
      LAYER M4 ;
        RECT  0 46.656 0.084 46.68 ;
    END
  END a[33]
  PIN a[34]
    DIRECTION INPUT ;
    USE SIGNAL ;
    PORT
      LAYER M4 ;
        RECT  0 46.8 0.084 46.824 ;
    END
  END a[34]
  PIN a[35]
    DIRECTION INPUT ;
    USE SIGNAL ;
    PORT
      LAYER M4 ;
        RECT  0 46.944 0.084 46.968 ;
    END
  END a[35]
  PIN a[36]
    DIRECTION INPUT ;
    USE SIGNAL ;
    PORT
      LAYER M4 ;
        RECT  0 47.088 0.084 47.112 ;
    END
  END a[36]
  PIN a[37]
    DIRECTION INPUT ;
    USE SIGNAL ;
    PORT
      LAYER M4 ;
        RECT  0 47.232 0.084 47.256 ;
    END
  END a[37]
  PIN a[38]
    DIRECTION INPUT ;
    USE SIGNAL ;
    PORT
      LAYER M4 ;
        RECT  0 47.376 0.084 47.4 ;
    END
  END a[38]
  PIN a[39]
    DIRECTION INPUT ;
    USE SIGNAL ;
    PORT
      LAYER M4 ;
        RECT  0 47.52 0.084 47.544 ;
    END
  END a[39]
  PIN a[3]
    DIRECTION INPUT ;
    USE SIGNAL ;
    PORT
      LAYER M4 ;
        RECT  0 28.512 0.084 28.536 ;
    END
  END a[3]
  PIN a[40]
    DIRECTION INPUT ;
    USE SIGNAL ;
    PORT
      LAYER M4 ;
        RECT  0 47.664 0.084 47.688 ;
    END
  END a[40]
  PIN a[41]
    DIRECTION INPUT ;
    USE SIGNAL ;
    PORT
      LAYER M4 ;
        RECT  0 47.808 0.084 47.832 ;
    END
  END a[41]
  PIN a[42]
    DIRECTION INPUT ;
    USE SIGNAL ;
    PORT
      LAYER M4 ;
        RECT  0 47.952 0.084 47.976 ;
    END
  END a[42]
  PIN a[43]
    DIRECTION INPUT ;
    USE SIGNAL ;
    PORT
      LAYER M4 ;
        RECT  0 48.096 0.084 48.12 ;
    END
  END a[43]
  PIN a[44]
    DIRECTION INPUT ;
    USE SIGNAL ;
    PORT
      LAYER M4 ;
        RECT  0 48.24 0.084 48.264 ;
    END
  END a[44]
  PIN a[45]
    DIRECTION INPUT ;
    USE SIGNAL ;
    PORT
      LAYER M4 ;
        RECT  0 48.384 0.084 48.408 ;
    END
  END a[45]
  PIN a[46]
    DIRECTION INPUT ;
    USE SIGNAL ;
    PORT
      LAYER M4 ;
        RECT  0 48.528 0.084 48.552 ;
    END
  END a[46]
  PIN a[47]
    DIRECTION INPUT ;
    USE SIGNAL ;
    PORT
      LAYER M4 ;
        RECT  0 48.672 0.084 48.696 ;
    END
  END a[47]
  PIN a[48]
    DIRECTION INPUT ;
    USE SIGNAL ;
    PORT
      LAYER M4 ;
        RECT  0 48.816 0.084 48.84 ;
    END
  END a[48]
  PIN a[49]
    DIRECTION INPUT ;
    USE SIGNAL ;
    PORT
      LAYER M4 ;
        RECT  0 48.96 0.084 48.984 ;
    END
  END a[49]
  PIN a[4]
    DIRECTION INPUT ;
    USE SIGNAL ;
    PORT
      LAYER M4 ;
        RECT  0 28.656 0.084 28.68 ;
    END
  END a[4]
  PIN a[50]
    DIRECTION INPUT ;
    USE SIGNAL ;
    PORT
      LAYER M4 ;
        RECT  0 49.104 0.084 49.128 ;
    END
  END a[50]
  PIN a[51]
    DIRECTION INPUT ;
    USE SIGNAL ;
    PORT
      LAYER M4 ;
        RECT  0 49.248 0.084 49.272 ;
    END
  END a[51]
  PIN a[52]
    DIRECTION INPUT ;
    USE SIGNAL ;
    PORT
      LAYER M4 ;
        RECT  0 49.392 0.084 49.416 ;
    END
  END a[52]
  PIN a[53]
    DIRECTION INPUT ;
    USE SIGNAL ;
    PORT
      LAYER M4 ;
        RECT  0 49.536 0.084 49.56 ;
    END
  END a[53]
  PIN a[54]
    DIRECTION INPUT ;
    USE SIGNAL ;
    PORT
      LAYER M4 ;
        RECT  0 49.68 0.084 49.704 ;
    END
  END a[54]
  PIN a[55]
    DIRECTION INPUT ;
    USE SIGNAL ;
    PORT
      LAYER M4 ;
        RECT  0 49.824 0.084 49.848 ;
    END
  END a[55]
  PIN a[56]
    DIRECTION INPUT ;
    USE SIGNAL ;
    PORT
      LAYER M4 ;
        RECT  0 49.968 0.084 49.992 ;
    END
  END a[56]
  PIN a[57]
    DIRECTION INPUT ;
    USE SIGNAL ;
    PORT
      LAYER M4 ;
        RECT  0 50.112 0.084 50.136 ;
    END
  END a[57]
  PIN a[58]
    DIRECTION INPUT ;
    USE SIGNAL ;
    PORT
      LAYER M4 ;
        RECT  0 50.256 0.084 50.28 ;
    END
  END a[58]
  PIN a[59]
    DIRECTION INPUT ;
    USE SIGNAL ;
    PORT
      LAYER M4 ;
        RECT  0 50.4 0.084 50.424 ;
    END
  END a[59]
  PIN a[5]
    DIRECTION INPUT ;
    USE SIGNAL ;
    PORT
      LAYER M4 ;
        RECT  0 28.8 0.084 28.824 ;
    END
  END a[5]
  PIN a[60]
    DIRECTION INPUT ;
    USE SIGNAL ;
    PORT
      LAYER M4 ;
        RECT  0 50.544 0.084 50.568 ;
    END
  END a[60]
  PIN a[61]
    DIRECTION INPUT ;
    USE SIGNAL ;
    PORT
      LAYER M4 ;
        RECT  0 50.688 0.084 50.712 ;
    END
  END a[61]
  PIN a[62]
    DIRECTION INPUT ;
    USE SIGNAL ;
    PORT
      LAYER M4 ;
        RECT  0 50.832 0.084 50.856 ;
    END
  END a[62]
  PIN a[63]
    DIRECTION INPUT ;
    USE SIGNAL ;
    PORT
      LAYER M4 ;
        RECT  0 50.976 0.084 51 ;
    END
  END a[63]
  PIN a[64]
    DIRECTION INPUT ;
    USE SIGNAL ;
    PORT
      LAYER M4 ;
        RECT  0 37.296 0.084 37.32 ;
    END
  END a[64]
  PIN a[65]
    DIRECTION INPUT ;
    USE SIGNAL ;
    PORT
      LAYER M4 ;
        RECT  0 37.44 0.084 37.464 ;
    END
  END a[65]
  PIN a[66]
    DIRECTION INPUT ;
    USE SIGNAL ;
    PORT
      LAYER M4 ;
        RECT  0 37.584 0.084 37.608 ;
    END
  END a[66]
  PIN a[67]
    DIRECTION INPUT ;
    USE SIGNAL ;
    PORT
      LAYER M4 ;
        RECT  0 37.728 0.084 37.752 ;
    END
  END a[67]
  PIN a[68]
    DIRECTION INPUT ;
    USE SIGNAL ;
    PORT
      LAYER M4 ;
        RECT  0 37.872 0.084 37.896 ;
    END
  END a[68]
  PIN a[69]
    DIRECTION INPUT ;
    USE SIGNAL ;
    PORT
      LAYER M4 ;
        RECT  0 38.016 0.084 38.04 ;
    END
  END a[69]
  PIN a[6]
    DIRECTION INPUT ;
    USE SIGNAL ;
    PORT
      LAYER M4 ;
        RECT  0 28.944 0.084 28.968 ;
    END
  END a[6]
  PIN a[70]
    DIRECTION INPUT ;
    USE SIGNAL ;
    PORT
      LAYER M4 ;
        RECT  0 38.16 0.084 38.184 ;
    END
  END a[70]
  PIN a[71]
    DIRECTION INPUT ;
    USE SIGNAL ;
    PORT
      LAYER M4 ;
        RECT  0 38.304 0.084 38.328 ;
    END
  END a[71]
  PIN a[72]
    DIRECTION INPUT ;
    USE SIGNAL ;
    PORT
      LAYER M4 ;
        RECT  0 38.448 0.084 38.472 ;
    END
  END a[72]
  PIN a[73]
    DIRECTION INPUT ;
    USE SIGNAL ;
    PORT
      LAYER M4 ;
        RECT  0 38.592 0.084 38.616 ;
    END
  END a[73]
  PIN a[74]
    DIRECTION INPUT ;
    USE SIGNAL ;
    PORT
      LAYER M4 ;
        RECT  0 38.736 0.084 38.76 ;
    END
  END a[74]
  PIN a[75]
    DIRECTION INPUT ;
    USE SIGNAL ;
    PORT
      LAYER M4 ;
        RECT  0 38.88 0.084 38.904 ;
    END
  END a[75]
  PIN a[76]
    DIRECTION INPUT ;
    USE SIGNAL ;
    PORT
      LAYER M4 ;
        RECT  0 39.024 0.084 39.048 ;
    END
  END a[76]
  PIN a[77]
    DIRECTION INPUT ;
    USE SIGNAL ;
    PORT
      LAYER M4 ;
        RECT  0 39.168 0.084 39.192 ;
    END
  END a[77]
  PIN a[78]
    DIRECTION INPUT ;
    USE SIGNAL ;
    PORT
      LAYER M4 ;
        RECT  0 39.312 0.084 39.336 ;
    END
  END a[78]
  PIN a[79]
    DIRECTION INPUT ;
    USE SIGNAL ;
    PORT
      LAYER M4 ;
        RECT  0 39.456 0.084 39.48 ;
    END
  END a[79]
  PIN a[7]
    DIRECTION INPUT ;
    USE SIGNAL ;
    PORT
      LAYER M4 ;
        RECT  0 29.088 0.084 29.112 ;
    END
  END a[7]
  PIN a[80]
    DIRECTION INPUT ;
    USE SIGNAL ;
    PORT
      LAYER M4 ;
        RECT  0 39.6 0.084 39.624 ;
    END
  END a[80]
  PIN a[81]
    DIRECTION INPUT ;
    USE SIGNAL ;
    PORT
      LAYER M4 ;
        RECT  0 39.744 0.084 39.768 ;
    END
  END a[81]
  PIN a[82]
    DIRECTION INPUT ;
    USE SIGNAL ;
    PORT
      LAYER M4 ;
        RECT  0 39.888 0.084 39.912 ;
    END
  END a[82]
  PIN a[83]
    DIRECTION INPUT ;
    USE SIGNAL ;
    PORT
      LAYER M4 ;
        RECT  0 40.032 0.084 40.056 ;
    END
  END a[83]
  PIN a[84]
    DIRECTION INPUT ;
    USE SIGNAL ;
    PORT
      LAYER M4 ;
        RECT  0 40.176 0.084 40.2 ;
    END
  END a[84]
  PIN a[85]
    DIRECTION INPUT ;
    USE SIGNAL ;
    PORT
      LAYER M4 ;
        RECT  0 40.32 0.084 40.344 ;
    END
  END a[85]
  PIN a[86]
    DIRECTION INPUT ;
    USE SIGNAL ;
    PORT
      LAYER M4 ;
        RECT  0 40.464 0.084 40.488 ;
    END
  END a[86]
  PIN a[87]
    DIRECTION INPUT ;
    USE SIGNAL ;
    PORT
      LAYER M4 ;
        RECT  0 40.608 0.084 40.632 ;
    END
  END a[87]
  PIN a[88]
    DIRECTION INPUT ;
    USE SIGNAL ;
    PORT
      LAYER M4 ;
        RECT  0 40.752 0.084 40.776 ;
    END
  END a[88]
  PIN a[89]
    DIRECTION INPUT ;
    USE SIGNAL ;
    PORT
      LAYER M4 ;
        RECT  0 40.896 0.084 40.92 ;
    END
  END a[89]
  PIN a[8]
    DIRECTION INPUT ;
    USE SIGNAL ;
    PORT
      LAYER M4 ;
        RECT  0 29.232 0.084 29.256 ;
    END
  END a[8]
  PIN a[90]
    DIRECTION INPUT ;
    USE SIGNAL ;
    PORT
      LAYER M4 ;
        RECT  0 41.04 0.084 41.064 ;
    END
  END a[90]
  PIN a[91]
    DIRECTION INPUT ;
    USE SIGNAL ;
    PORT
      LAYER M4 ;
        RECT  0 41.184 0.084 41.208 ;
    END
  END a[91]
  PIN a[92]
    DIRECTION INPUT ;
    USE SIGNAL ;
    PORT
      LAYER M4 ;
        RECT  0 41.328 0.084 41.352 ;
    END
  END a[92]
  PIN a[93]
    DIRECTION INPUT ;
    USE SIGNAL ;
    PORT
      LAYER M4 ;
        RECT  0 41.472 0.084 41.496 ;
    END
  END a[93]
  PIN a[94]
    DIRECTION INPUT ;
    USE SIGNAL ;
    PORT
      LAYER M4 ;
        RECT  0 41.616 0.084 41.64 ;
    END
  END a[94]
  PIN a[95]
    DIRECTION INPUT ;
    USE SIGNAL ;
    PORT
      LAYER M4 ;
        RECT  0 41.76 0.084 41.784 ;
    END
  END a[95]
  PIN a[96]
    DIRECTION INPUT ;
    USE SIGNAL ;
    PORT
      LAYER M4 ;
        RECT  0 23.472 0.084 23.496 ;
    END
  END a[96]
  PIN a[97]
    DIRECTION INPUT ;
    USE SIGNAL ;
    PORT
      LAYER M4 ;
        RECT  0 23.616 0.084 23.64 ;
    END
  END a[97]
  PIN a[98]
    DIRECTION INPUT ;
    USE SIGNAL ;
    PORT
      LAYER M4 ;
        RECT  0 23.76 0.084 23.784 ;
    END
  END a[98]
  PIN a[99]
    DIRECTION INPUT ;
    USE SIGNAL ;
    PORT
      LAYER M4 ;
        RECT  0 23.904 0.084 23.928 ;
    END
  END a[99]
  PIN a[9]
    DIRECTION INPUT ;
    USE SIGNAL ;
    PORT
      LAYER M4 ;
        RECT  0 29.376 0.084 29.4 ;
    END
  END a[9]
  PIN b[0]
    DIRECTION OUTPUT ;
    USE SIGNAL ;
    PORT
      LAYER M4 ;
        RECT  25.836 0.72 25.92 0.744 ;
    END
  END b[0]
  PIN b[100]
    DIRECTION OUTPUT ;
    USE SIGNAL ;
    PORT
      LAYER M4 ;
        RECT  25.836 10.512 25.92 10.536 ;
    END
  END b[100]
  PIN b[101]
    DIRECTION OUTPUT ;
    USE SIGNAL ;
    PORT
      LAYER M4 ;
        RECT  25.836 10.656 25.92 10.68 ;
    END
  END b[101]
  PIN b[102]
    DIRECTION OUTPUT ;
    USE SIGNAL ;
    PORT
      LAYER M4 ;
        RECT  25.836 10.8 25.92 10.824 ;
    END
  END b[102]
  PIN b[103]
    DIRECTION OUTPUT ;
    USE SIGNAL ;
    PORT
      LAYER M4 ;
        RECT  25.836 10.944 25.92 10.968 ;
    END
  END b[103]
  PIN b[104]
    DIRECTION OUTPUT ;
    USE SIGNAL ;
    PORT
      LAYER M4 ;
        RECT  25.836 11.088 25.92 11.112 ;
    END
  END b[104]
  PIN b[105]
    DIRECTION OUTPUT ;
    USE SIGNAL ;
    PORT
      LAYER M4 ;
        RECT  25.836 11.232 25.92 11.256 ;
    END
  END b[105]
  PIN b[106]
    DIRECTION OUTPUT ;
    USE SIGNAL ;
    PORT
      LAYER M4 ;
        RECT  25.836 11.376 25.92 11.4 ;
    END
  END b[106]
  PIN b[107]
    DIRECTION OUTPUT ;
    USE SIGNAL ;
    PORT
      LAYER M4 ;
        RECT  25.836 11.52 25.92 11.544 ;
    END
  END b[107]
  PIN b[108]
    DIRECTION OUTPUT ;
    USE SIGNAL ;
    PORT
      LAYER M4 ;
        RECT  25.836 11.664 25.92 11.688 ;
    END
  END b[108]
  PIN b[109]
    DIRECTION OUTPUT ;
    USE SIGNAL ;
    PORT
      LAYER M4 ;
        RECT  25.836 11.808 25.92 11.832 ;
    END
  END b[109]
  PIN b[10]
    DIRECTION OUTPUT ;
    USE SIGNAL ;
    PORT
      LAYER M4 ;
        RECT  25.836 2.16 25.92 2.184 ;
    END
  END b[10]
  PIN b[110]
    DIRECTION OUTPUT ;
    USE SIGNAL ;
    PORT
      LAYER M4 ;
        RECT  25.836 11.952 25.92 11.976 ;
    END
  END b[110]
  PIN b[111]
    DIRECTION OUTPUT ;
    USE SIGNAL ;
    PORT
      LAYER M4 ;
        RECT  25.836 12.096 25.92 12.12 ;
    END
  END b[111]
  PIN b[112]
    DIRECTION OUTPUT ;
    USE SIGNAL ;
    PORT
      LAYER M4 ;
        RECT  25.836 12.24 25.92 12.264 ;
    END
  END b[112]
  PIN b[113]
    DIRECTION OUTPUT ;
    USE SIGNAL ;
    PORT
      LAYER M4 ;
        RECT  25.836 12.384 25.92 12.408 ;
    END
  END b[113]
  PIN b[114]
    DIRECTION OUTPUT ;
    USE SIGNAL ;
    PORT
      LAYER M4 ;
        RECT  25.836 12.528 25.92 12.552 ;
    END
  END b[114]
  PIN b[115]
    DIRECTION OUTPUT ;
    USE SIGNAL ;
    PORT
      LAYER M4 ;
        RECT  25.836 12.672 25.92 12.696 ;
    END
  END b[115]
  PIN b[116]
    DIRECTION OUTPUT ;
    USE SIGNAL ;
    PORT
      LAYER M4 ;
        RECT  25.836 12.816 25.92 12.84 ;
    END
  END b[116]
  PIN b[117]
    DIRECTION OUTPUT ;
    USE SIGNAL ;
    PORT
      LAYER M4 ;
        RECT  25.836 12.96 25.92 12.984 ;
    END
  END b[117]
  PIN b[118]
    DIRECTION OUTPUT ;
    USE SIGNAL ;
    PORT
      LAYER M4 ;
        RECT  25.836 13.104 25.92 13.128 ;
    END
  END b[118]
  PIN b[119]
    DIRECTION OUTPUT ;
    USE SIGNAL ;
    PORT
      LAYER M4 ;
        RECT  25.836 13.248 25.92 13.272 ;
    END
  END b[119]
  PIN b[11]
    DIRECTION OUTPUT ;
    USE SIGNAL ;
    PORT
      LAYER M4 ;
        RECT  25.836 2.304 25.92 2.328 ;
    END
  END b[11]
  PIN b[120]
    DIRECTION OUTPUT ;
    USE SIGNAL ;
    PORT
      LAYER M4 ;
        RECT  25.836 13.392 25.92 13.416 ;
    END
  END b[120]
  PIN b[121]
    DIRECTION OUTPUT ;
    USE SIGNAL ;
    PORT
      LAYER M4 ;
        RECT  25.836 13.536 25.92 13.56 ;
    END
  END b[121]
  PIN b[122]
    DIRECTION OUTPUT ;
    USE SIGNAL ;
    PORT
      LAYER M4 ;
        RECT  25.836 13.68 25.92 13.704 ;
    END
  END b[122]
  PIN b[123]
    DIRECTION OUTPUT ;
    USE SIGNAL ;
    PORT
      LAYER M4 ;
        RECT  25.836 13.824 25.92 13.848 ;
    END
  END b[123]
  PIN b[124]
    DIRECTION OUTPUT ;
    USE SIGNAL ;
    PORT
      LAYER M4 ;
        RECT  25.836 13.968 25.92 13.992 ;
    END
  END b[124]
  PIN b[125]
    DIRECTION OUTPUT ;
    USE SIGNAL ;
    PORT
      LAYER M4 ;
        RECT  25.836 14.112 25.92 14.136 ;
    END
  END b[125]
  PIN b[126]
    DIRECTION OUTPUT ;
    USE SIGNAL ;
    PORT
      LAYER M4 ;
        RECT  25.836 14.256 25.92 14.28 ;
    END
  END b[126]
  PIN b[127]
    DIRECTION OUTPUT ;
    USE SIGNAL ;
    PORT
      LAYER M4 ;
        RECT  25.836 14.4 25.92 14.424 ;
    END
  END b[127]
  PIN b[128]
    DIRECTION OUTPUT ;
    USE SIGNAL ;
    PORT
      LAYER M4 ;
        RECT  25.836 19.152 25.92 19.176 ;
    END
  END b[128]
  PIN b[129]
    DIRECTION OUTPUT ;
    USE SIGNAL ;
    PORT
      LAYER M4 ;
        RECT  25.836 19.296 25.92 19.32 ;
    END
  END b[129]
  PIN b[12]
    DIRECTION OUTPUT ;
    USE SIGNAL ;
    PORT
      LAYER M4 ;
        RECT  25.836 2.448 25.92 2.472 ;
    END
  END b[12]
  PIN b[130]
    DIRECTION OUTPUT ;
    USE SIGNAL ;
    PORT
      LAYER M4 ;
        RECT  25.836 19.44 25.92 19.464 ;
    END
  END b[130]
  PIN b[131]
    DIRECTION OUTPUT ;
    USE SIGNAL ;
    PORT
      LAYER M4 ;
        RECT  25.836 19.584 25.92 19.608 ;
    END
  END b[131]
  PIN b[132]
    DIRECTION OUTPUT ;
    USE SIGNAL ;
    PORT
      LAYER M4 ;
        RECT  25.836 19.728 25.92 19.752 ;
    END
  END b[132]
  PIN b[133]
    DIRECTION OUTPUT ;
    USE SIGNAL ;
    PORT
      LAYER M4 ;
        RECT  25.836 19.872 25.92 19.896 ;
    END
  END b[133]
  PIN b[134]
    DIRECTION OUTPUT ;
    USE SIGNAL ;
    PORT
      LAYER M4 ;
        RECT  25.836 20.016 25.92 20.04 ;
    END
  END b[134]
  PIN b[135]
    DIRECTION OUTPUT ;
    USE SIGNAL ;
    PORT
      LAYER M4 ;
        RECT  25.836 20.16 25.92 20.184 ;
    END
  END b[135]
  PIN b[136]
    DIRECTION OUTPUT ;
    USE SIGNAL ;
    PORT
      LAYER M4 ;
        RECT  25.836 20.304 25.92 20.328 ;
    END
  END b[136]
  PIN b[137]
    DIRECTION OUTPUT ;
    USE SIGNAL ;
    PORT
      LAYER M4 ;
        RECT  25.836 20.448 25.92 20.472 ;
    END
  END b[137]
  PIN b[138]
    DIRECTION OUTPUT ;
    USE SIGNAL ;
    PORT
      LAYER M4 ;
        RECT  25.836 20.592 25.92 20.616 ;
    END
  END b[138]
  PIN b[139]
    DIRECTION OUTPUT ;
    USE SIGNAL ;
    PORT
      LAYER M4 ;
        RECT  25.836 20.736 25.92 20.76 ;
    END
  END b[139]
  PIN b[13]
    DIRECTION OUTPUT ;
    USE SIGNAL ;
    PORT
      LAYER M4 ;
        RECT  25.836 2.592 25.92 2.616 ;
    END
  END b[13]
  PIN b[140]
    DIRECTION OUTPUT ;
    USE SIGNAL ;
    PORT
      LAYER M4 ;
        RECT  25.836 20.88 25.92 20.904 ;
    END
  END b[140]
  PIN b[141]
    DIRECTION OUTPUT ;
    USE SIGNAL ;
    PORT
      LAYER M4 ;
        RECT  25.836 21.024 25.92 21.048 ;
    END
  END b[141]
  PIN b[142]
    DIRECTION OUTPUT ;
    USE SIGNAL ;
    PORT
      LAYER M4 ;
        RECT  25.836 21.168 25.92 21.192 ;
    END
  END b[142]
  PIN b[143]
    DIRECTION OUTPUT ;
    USE SIGNAL ;
    PORT
      LAYER M4 ;
        RECT  25.836 21.312 25.92 21.336 ;
    END
  END b[143]
  PIN b[144]
    DIRECTION OUTPUT ;
    USE SIGNAL ;
    PORT
      LAYER M4 ;
        RECT  25.836 21.456 25.92 21.48 ;
    END
  END b[144]
  PIN b[145]
    DIRECTION OUTPUT ;
    USE SIGNAL ;
    PORT
      LAYER M4 ;
        RECT  25.836 21.6 25.92 21.624 ;
    END
  END b[145]
  PIN b[146]
    DIRECTION OUTPUT ;
    USE SIGNAL ;
    PORT
      LAYER M4 ;
        RECT  25.836 21.744 25.92 21.768 ;
    END
  END b[146]
  PIN b[147]
    DIRECTION OUTPUT ;
    USE SIGNAL ;
    PORT
      LAYER M4 ;
        RECT  25.836 21.888 25.92 21.912 ;
    END
  END b[147]
  PIN b[148]
    DIRECTION OUTPUT ;
    USE SIGNAL ;
    PORT
      LAYER M4 ;
        RECT  25.836 22.032 25.92 22.056 ;
    END
  END b[148]
  PIN b[149]
    DIRECTION OUTPUT ;
    USE SIGNAL ;
    PORT
      LAYER M4 ;
        RECT  25.836 22.176 25.92 22.2 ;
    END
  END b[149]
  PIN b[14]
    DIRECTION OUTPUT ;
    USE SIGNAL ;
    PORT
      LAYER M4 ;
        RECT  25.836 2.736 25.92 2.76 ;
    END
  END b[14]
  PIN b[150]
    DIRECTION OUTPUT ;
    USE SIGNAL ;
    PORT
      LAYER M4 ;
        RECT  25.836 22.32 25.92 22.344 ;
    END
  END b[150]
  PIN b[151]
    DIRECTION OUTPUT ;
    USE SIGNAL ;
    PORT
      LAYER M4 ;
        RECT  25.836 22.464 25.92 22.488 ;
    END
  END b[151]
  PIN b[152]
    DIRECTION OUTPUT ;
    USE SIGNAL ;
    PORT
      LAYER M4 ;
        RECT  25.836 22.608 25.92 22.632 ;
    END
  END b[152]
  PIN b[153]
    DIRECTION OUTPUT ;
    USE SIGNAL ;
    PORT
      LAYER M4 ;
        RECT  25.836 22.752 25.92 22.776 ;
    END
  END b[153]
  PIN b[154]
    DIRECTION OUTPUT ;
    USE SIGNAL ;
    PORT
      LAYER M4 ;
        RECT  25.836 22.896 25.92 22.92 ;
    END
  END b[154]
  PIN b[155]
    DIRECTION OUTPUT ;
    USE SIGNAL ;
    PORT
      LAYER M4 ;
        RECT  25.836 23.04 25.92 23.064 ;
    END
  END b[155]
  PIN b[156]
    DIRECTION OUTPUT ;
    USE SIGNAL ;
    PORT
      LAYER M4 ;
        RECT  25.836 23.184 25.92 23.208 ;
    END
  END b[156]
  PIN b[157]
    DIRECTION OUTPUT ;
    USE SIGNAL ;
    PORT
      LAYER M4 ;
        RECT  25.836 23.328 25.92 23.352 ;
    END
  END b[157]
  PIN b[158]
    DIRECTION OUTPUT ;
    USE SIGNAL ;
    PORT
      LAYER M4 ;
        RECT  25.836 23.472 25.92 23.496 ;
    END
  END b[158]
  PIN b[159]
    DIRECTION OUTPUT ;
    USE SIGNAL ;
    PORT
      LAYER M4 ;
        RECT  25.836 23.616 25.92 23.64 ;
    END
  END b[159]
  PIN b[15]
    DIRECTION OUTPUT ;
    USE SIGNAL ;
    PORT
      LAYER M4 ;
        RECT  25.836 2.88 25.92 2.904 ;
    END
  END b[15]
  PIN b[160]
    DIRECTION OUTPUT ;
    USE SIGNAL ;
    PORT
      LAYER M4 ;
        RECT  25.836 14.544 25.92 14.568 ;
    END
  END b[160]
  PIN b[161]
    DIRECTION OUTPUT ;
    USE SIGNAL ;
    PORT
      LAYER M4 ;
        RECT  25.836 14.688 25.92 14.712 ;
    END
  END b[161]
  PIN b[162]
    DIRECTION OUTPUT ;
    USE SIGNAL ;
    PORT
      LAYER M4 ;
        RECT  25.836 14.832 25.92 14.856 ;
    END
  END b[162]
  PIN b[163]
    DIRECTION OUTPUT ;
    USE SIGNAL ;
    PORT
      LAYER M4 ;
        RECT  25.836 14.976 25.92 15 ;
    END
  END b[163]
  PIN b[164]
    DIRECTION OUTPUT ;
    USE SIGNAL ;
    PORT
      LAYER M4 ;
        RECT  25.836 15.12 25.92 15.144 ;
    END
  END b[164]
  PIN b[165]
    DIRECTION OUTPUT ;
    USE SIGNAL ;
    PORT
      LAYER M4 ;
        RECT  25.836 15.264 25.92 15.288 ;
    END
  END b[165]
  PIN b[166]
    DIRECTION OUTPUT ;
    USE SIGNAL ;
    PORT
      LAYER M4 ;
        RECT  25.836 15.408 25.92 15.432 ;
    END
  END b[166]
  PIN b[167]
    DIRECTION OUTPUT ;
    USE SIGNAL ;
    PORT
      LAYER M4 ;
        RECT  25.836 15.552 25.92 15.576 ;
    END
  END b[167]
  PIN b[168]
    DIRECTION OUTPUT ;
    USE SIGNAL ;
    PORT
      LAYER M4 ;
        RECT  25.836 15.696 25.92 15.72 ;
    END
  END b[168]
  PIN b[169]
    DIRECTION OUTPUT ;
    USE SIGNAL ;
    PORT
      LAYER M4 ;
        RECT  25.836 15.84 25.92 15.864 ;
    END
  END b[169]
  PIN b[16]
    DIRECTION OUTPUT ;
    USE SIGNAL ;
    PORT
      LAYER M4 ;
        RECT  25.836 3.024 25.92 3.048 ;
    END
  END b[16]
  PIN b[170]
    DIRECTION OUTPUT ;
    USE SIGNAL ;
    PORT
      LAYER M4 ;
        RECT  25.836 15.984 25.92 16.008 ;
    END
  END b[170]
  PIN b[171]
    DIRECTION OUTPUT ;
    USE SIGNAL ;
    PORT
      LAYER M4 ;
        RECT  25.836 16.128 25.92 16.152 ;
    END
  END b[171]
  PIN b[172]
    DIRECTION OUTPUT ;
    USE SIGNAL ;
    PORT
      LAYER M4 ;
        RECT  25.836 16.272 25.92 16.296 ;
    END
  END b[172]
  PIN b[173]
    DIRECTION OUTPUT ;
    USE SIGNAL ;
    PORT
      LAYER M4 ;
        RECT  25.836 16.416 25.92 16.44 ;
    END
  END b[173]
  PIN b[174]
    DIRECTION OUTPUT ;
    USE SIGNAL ;
    PORT
      LAYER M4 ;
        RECT  25.836 16.56 25.92 16.584 ;
    END
  END b[174]
  PIN b[175]
    DIRECTION OUTPUT ;
    USE SIGNAL ;
    PORT
      LAYER M4 ;
        RECT  25.836 16.704 25.92 16.728 ;
    END
  END b[175]
  PIN b[176]
    DIRECTION OUTPUT ;
    USE SIGNAL ;
    PORT
      LAYER M4 ;
        RECT  25.836 16.848 25.92 16.872 ;
    END
  END b[176]
  PIN b[177]
    DIRECTION OUTPUT ;
    USE SIGNAL ;
    PORT
      LAYER M4 ;
        RECT  25.836 16.992 25.92 17.016 ;
    END
  END b[177]
  PIN b[178]
    DIRECTION OUTPUT ;
    USE SIGNAL ;
    PORT
      LAYER M4 ;
        RECT  25.836 17.136 25.92 17.16 ;
    END
  END b[178]
  PIN b[179]
    DIRECTION OUTPUT ;
    USE SIGNAL ;
    PORT
      LAYER M4 ;
        RECT  25.836 17.28 25.92 17.304 ;
    END
  END b[179]
  PIN b[17]
    DIRECTION OUTPUT ;
    USE SIGNAL ;
    PORT
      LAYER M4 ;
        RECT  25.836 3.168 25.92 3.192 ;
    END
  END b[17]
  PIN b[180]
    DIRECTION OUTPUT ;
    USE SIGNAL ;
    PORT
      LAYER M4 ;
        RECT  25.836 17.424 25.92 17.448 ;
    END
  END b[180]
  PIN b[181]
    DIRECTION OUTPUT ;
    USE SIGNAL ;
    PORT
      LAYER M4 ;
        RECT  25.836 17.568 25.92 17.592 ;
    END
  END b[181]
  PIN b[182]
    DIRECTION OUTPUT ;
    USE SIGNAL ;
    PORT
      LAYER M4 ;
        RECT  25.836 17.712 25.92 17.736 ;
    END
  END b[182]
  PIN b[183]
    DIRECTION OUTPUT ;
    USE SIGNAL ;
    PORT
      LAYER M4 ;
        RECT  25.836 17.856 25.92 17.88 ;
    END
  END b[183]
  PIN b[184]
    DIRECTION OUTPUT ;
    USE SIGNAL ;
    PORT
      LAYER M4 ;
        RECT  25.836 18 25.92 18.024 ;
    END
  END b[184]
  PIN b[185]
    DIRECTION OUTPUT ;
    USE SIGNAL ;
    PORT
      LAYER M4 ;
        RECT  25.836 18.144 25.92 18.168 ;
    END
  END b[185]
  PIN b[186]
    DIRECTION OUTPUT ;
    USE SIGNAL ;
    PORT
      LAYER M4 ;
        RECT  25.836 18.288 25.92 18.312 ;
    END
  END b[186]
  PIN b[187]
    DIRECTION OUTPUT ;
    USE SIGNAL ;
    PORT
      LAYER M4 ;
        RECT  25.836 18.432 25.92 18.456 ;
    END
  END b[187]
  PIN b[188]
    DIRECTION OUTPUT ;
    USE SIGNAL ;
    PORT
      LAYER M4 ;
        RECT  25.836 18.576 25.92 18.6 ;
    END
  END b[188]
  PIN b[189]
    DIRECTION OUTPUT ;
    USE SIGNAL ;
    PORT
      LAYER M4 ;
        RECT  25.836 18.72 25.92 18.744 ;
    END
  END b[189]
  PIN b[18]
    DIRECTION OUTPUT ;
    USE SIGNAL ;
    PORT
      LAYER M4 ;
        RECT  25.836 3.312 25.92 3.336 ;
    END
  END b[18]
  PIN b[190]
    DIRECTION OUTPUT ;
    USE SIGNAL ;
    PORT
      LAYER M4 ;
        RECT  25.836 18.864 25.92 18.888 ;
    END
  END b[190]
  PIN b[191]
    DIRECTION OUTPUT ;
    USE SIGNAL ;
    PORT
      LAYER M4 ;
        RECT  25.836 19.008 25.92 19.032 ;
    END
  END b[191]
  PIN b[192]
    DIRECTION OUTPUT ;
    USE SIGNAL ;
    PORT
      LAYER M4 ;
        RECT  25.836 29.52 25.92 29.544 ;
    END
  END b[192]
  PIN b[193]
    DIRECTION OUTPUT ;
    USE SIGNAL ;
    PORT
      LAYER M4 ;
        RECT  25.836 29.664 25.92 29.688 ;
    END
  END b[193]
  PIN b[194]
    DIRECTION OUTPUT ;
    USE SIGNAL ;
    PORT
      LAYER M4 ;
        RECT  25.836 29.808 25.92 29.832 ;
    END
  END b[194]
  PIN b[195]
    DIRECTION OUTPUT ;
    USE SIGNAL ;
    PORT
      LAYER M4 ;
        RECT  25.836 29.952 25.92 29.976 ;
    END
  END b[195]
  PIN b[196]
    DIRECTION OUTPUT ;
    USE SIGNAL ;
    PORT
      LAYER M4 ;
        RECT  25.836 30.096 25.92 30.12 ;
    END
  END b[196]
  PIN b[197]
    DIRECTION OUTPUT ;
    USE SIGNAL ;
    PORT
      LAYER M4 ;
        RECT  25.836 30.24 25.92 30.264 ;
    END
  END b[197]
  PIN b[198]
    DIRECTION OUTPUT ;
    USE SIGNAL ;
    PORT
      LAYER M4 ;
        RECT  25.836 30.384 25.92 30.408 ;
    END
  END b[198]
  PIN b[199]
    DIRECTION OUTPUT ;
    USE SIGNAL ;
    PORT
      LAYER M4 ;
        RECT  25.836 30.528 25.92 30.552 ;
    END
  END b[199]
  PIN b[19]
    DIRECTION OUTPUT ;
    USE SIGNAL ;
    PORT
      LAYER M4 ;
        RECT  25.836 3.456 25.92 3.48 ;
    END
  END b[19]
  PIN b[1]
    DIRECTION OUTPUT ;
    USE SIGNAL ;
    PORT
      LAYER M4 ;
        RECT  25.836 0.864 25.92 0.888 ;
    END
  END b[1]
  PIN b[200]
    DIRECTION OUTPUT ;
    USE SIGNAL ;
    PORT
      LAYER M4 ;
        RECT  25.836 30.672 25.92 30.696 ;
    END
  END b[200]
  PIN b[201]
    DIRECTION OUTPUT ;
    USE SIGNAL ;
    PORT
      LAYER M4 ;
        RECT  25.836 30.816 25.92 30.84 ;
    END
  END b[201]
  PIN b[202]
    DIRECTION OUTPUT ;
    USE SIGNAL ;
    PORT
      LAYER M4 ;
        RECT  25.836 30.96 25.92 30.984 ;
    END
  END b[202]
  PIN b[203]
    DIRECTION OUTPUT ;
    USE SIGNAL ;
    PORT
      LAYER M4 ;
        RECT  25.836 31.104 25.92 31.128 ;
    END
  END b[203]
  PIN b[204]
    DIRECTION OUTPUT ;
    USE SIGNAL ;
    PORT
      LAYER M4 ;
        RECT  25.836 31.248 25.92 31.272 ;
    END
  END b[204]
  PIN b[205]
    DIRECTION OUTPUT ;
    USE SIGNAL ;
    PORT
      LAYER M4 ;
        RECT  25.836 31.392 25.92 31.416 ;
    END
  END b[205]
  PIN b[206]
    DIRECTION OUTPUT ;
    USE SIGNAL ;
    PORT
      LAYER M4 ;
        RECT  25.836 31.536 25.92 31.56 ;
    END
  END b[206]
  PIN b[207]
    DIRECTION OUTPUT ;
    USE SIGNAL ;
    PORT
      LAYER M4 ;
        RECT  25.836 31.68 25.92 31.704 ;
    END
  END b[207]
  PIN b[208]
    DIRECTION OUTPUT ;
    USE SIGNAL ;
    PORT
      LAYER M4 ;
        RECT  25.836 31.824 25.92 31.848 ;
    END
  END b[208]
  PIN b[209]
    DIRECTION OUTPUT ;
    USE SIGNAL ;
    PORT
      LAYER M4 ;
        RECT  25.836 31.968 25.92 31.992 ;
    END
  END b[209]
  PIN b[20]
    DIRECTION OUTPUT ;
    USE SIGNAL ;
    PORT
      LAYER M4 ;
        RECT  25.836 3.6 25.92 3.624 ;
    END
  END b[20]
  PIN b[210]
    DIRECTION OUTPUT ;
    USE SIGNAL ;
    PORT
      LAYER M4 ;
        RECT  25.836 32.112 25.92 32.136 ;
    END
  END b[210]
  PIN b[211]
    DIRECTION OUTPUT ;
    USE SIGNAL ;
    PORT
      LAYER M4 ;
        RECT  25.836 32.256 25.92 32.28 ;
    END
  END b[211]
  PIN b[212]
    DIRECTION OUTPUT ;
    USE SIGNAL ;
    PORT
      LAYER M4 ;
        RECT  25.836 32.4 25.92 32.424 ;
    END
  END b[212]
  PIN b[213]
    DIRECTION OUTPUT ;
    USE SIGNAL ;
    PORT
      LAYER M4 ;
        RECT  25.836 32.544 25.92 32.568 ;
    END
  END b[213]
  PIN b[214]
    DIRECTION OUTPUT ;
    USE SIGNAL ;
    PORT
      LAYER M4 ;
        RECT  25.836 32.688 25.92 32.712 ;
    END
  END b[214]
  PIN b[215]
    DIRECTION OUTPUT ;
    USE SIGNAL ;
    PORT
      LAYER M4 ;
        RECT  25.836 32.832 25.92 32.856 ;
    END
  END b[215]
  PIN b[216]
    DIRECTION OUTPUT ;
    USE SIGNAL ;
    PORT
      LAYER M4 ;
        RECT  25.836 32.976 25.92 33 ;
    END
  END b[216]
  PIN b[217]
    DIRECTION OUTPUT ;
    USE SIGNAL ;
    PORT
      LAYER M4 ;
        RECT  25.836 33.12 25.92 33.144 ;
    END
  END b[217]
  PIN b[218]
    DIRECTION OUTPUT ;
    USE SIGNAL ;
    PORT
      LAYER M4 ;
        RECT  25.836 33.264 25.92 33.288 ;
    END
  END b[218]
  PIN b[219]
    DIRECTION OUTPUT ;
    USE SIGNAL ;
    PORT
      LAYER M4 ;
        RECT  25.836 33.408 25.92 33.432 ;
    END
  END b[219]
  PIN b[21]
    DIRECTION OUTPUT ;
    USE SIGNAL ;
    PORT
      LAYER M4 ;
        RECT  25.836 3.744 25.92 3.768 ;
    END
  END b[21]
  PIN b[220]
    DIRECTION OUTPUT ;
    USE SIGNAL ;
    PORT
      LAYER M4 ;
        RECT  25.836 33.552 25.92 33.576 ;
    END
  END b[220]
  PIN b[221]
    DIRECTION OUTPUT ;
    USE SIGNAL ;
    PORT
      LAYER M4 ;
        RECT  25.836 33.696 25.92 33.72 ;
    END
  END b[221]
  PIN b[222]
    DIRECTION OUTPUT ;
    USE SIGNAL ;
    PORT
      LAYER M4 ;
        RECT  25.836 33.84 25.92 33.864 ;
    END
  END b[222]
  PIN b[223]
    DIRECTION OUTPUT ;
    USE SIGNAL ;
    PORT
      LAYER M4 ;
        RECT  25.836 33.984 25.92 34.008 ;
    END
  END b[223]
  PIN b[224]
    DIRECTION OUTPUT ;
    USE SIGNAL ;
    PORT
      LAYER M4 ;
        RECT  25.836 38.736 25.92 38.76 ;
    END
  END b[224]
  PIN b[225]
    DIRECTION OUTPUT ;
    USE SIGNAL ;
    PORT
      LAYER M4 ;
        RECT  25.836 38.88 25.92 38.904 ;
    END
  END b[225]
  PIN b[226]
    DIRECTION OUTPUT ;
    USE SIGNAL ;
    PORT
      LAYER M4 ;
        RECT  25.836 39.024 25.92 39.048 ;
    END
  END b[226]
  PIN b[227]
    DIRECTION OUTPUT ;
    USE SIGNAL ;
    PORT
      LAYER M4 ;
        RECT  25.836 39.168 25.92 39.192 ;
    END
  END b[227]
  PIN b[228]
    DIRECTION OUTPUT ;
    USE SIGNAL ;
    PORT
      LAYER M4 ;
        RECT  25.836 39.312 25.92 39.336 ;
    END
  END b[228]
  PIN b[229]
    DIRECTION OUTPUT ;
    USE SIGNAL ;
    PORT
      LAYER M4 ;
        RECT  25.836 39.456 25.92 39.48 ;
    END
  END b[229]
  PIN b[22]
    DIRECTION OUTPUT ;
    USE SIGNAL ;
    PORT
      LAYER M4 ;
        RECT  25.836 3.888 25.92 3.912 ;
    END
  END b[22]
  PIN b[230]
    DIRECTION OUTPUT ;
    USE SIGNAL ;
    PORT
      LAYER M4 ;
        RECT  25.836 39.6 25.92 39.624 ;
    END
  END b[230]
  PIN b[231]
    DIRECTION OUTPUT ;
    USE SIGNAL ;
    PORT
      LAYER M4 ;
        RECT  25.836 39.744 25.92 39.768 ;
    END
  END b[231]
  PIN b[232]
    DIRECTION OUTPUT ;
    USE SIGNAL ;
    PORT
      LAYER M4 ;
        RECT  25.836 39.888 25.92 39.912 ;
    END
  END b[232]
  PIN b[233]
    DIRECTION OUTPUT ;
    USE SIGNAL ;
    PORT
      LAYER M4 ;
        RECT  25.836 40.032 25.92 40.056 ;
    END
  END b[233]
  PIN b[234]
    DIRECTION OUTPUT ;
    USE SIGNAL ;
    PORT
      LAYER M4 ;
        RECT  25.836 40.176 25.92 40.2 ;
    END
  END b[234]
  PIN b[235]
    DIRECTION OUTPUT ;
    USE SIGNAL ;
    PORT
      LAYER M4 ;
        RECT  25.836 40.32 25.92 40.344 ;
    END
  END b[235]
  PIN b[236]
    DIRECTION OUTPUT ;
    USE SIGNAL ;
    PORT
      LAYER M4 ;
        RECT  25.836 40.464 25.92 40.488 ;
    END
  END b[236]
  PIN b[237]
    DIRECTION OUTPUT ;
    USE SIGNAL ;
    PORT
      LAYER M4 ;
        RECT  25.836 40.608 25.92 40.632 ;
    END
  END b[237]
  PIN b[238]
    DIRECTION OUTPUT ;
    USE SIGNAL ;
    PORT
      LAYER M4 ;
        RECT  25.836 40.752 25.92 40.776 ;
    END
  END b[238]
  PIN b[239]
    DIRECTION OUTPUT ;
    USE SIGNAL ;
    PORT
      LAYER M4 ;
        RECT  25.836 40.896 25.92 40.92 ;
    END
  END b[239]
  PIN b[23]
    DIRECTION OUTPUT ;
    USE SIGNAL ;
    PORT
      LAYER M4 ;
        RECT  25.836 4.032 25.92 4.056 ;
    END
  END b[23]
  PIN b[240]
    DIRECTION OUTPUT ;
    USE SIGNAL ;
    PORT
      LAYER M4 ;
        RECT  25.836 41.04 25.92 41.064 ;
    END
  END b[240]
  PIN b[241]
    DIRECTION OUTPUT ;
    USE SIGNAL ;
    PORT
      LAYER M4 ;
        RECT  25.836 41.184 25.92 41.208 ;
    END
  END b[241]
  PIN b[242]
    DIRECTION OUTPUT ;
    USE SIGNAL ;
    PORT
      LAYER M4 ;
        RECT  25.836 41.328 25.92 41.352 ;
    END
  END b[242]
  PIN b[243]
    DIRECTION OUTPUT ;
    USE SIGNAL ;
    PORT
      LAYER M4 ;
        RECT  25.836 41.472 25.92 41.496 ;
    END
  END b[243]
  PIN b[244]
    DIRECTION OUTPUT ;
    USE SIGNAL ;
    PORT
      LAYER M4 ;
        RECT  25.836 41.616 25.92 41.64 ;
    END
  END b[244]
  PIN b[245]
    DIRECTION OUTPUT ;
    USE SIGNAL ;
    PORT
      LAYER M4 ;
        RECT  25.836 41.76 25.92 41.784 ;
    END
  END b[245]
  PIN b[246]
    DIRECTION OUTPUT ;
    USE SIGNAL ;
    PORT
      LAYER M4 ;
        RECT  25.836 41.904 25.92 41.928 ;
    END
  END b[246]
  PIN b[247]
    DIRECTION OUTPUT ;
    USE SIGNAL ;
    PORT
      LAYER M4 ;
        RECT  25.836 42.048 25.92 42.072 ;
    END
  END b[247]
  PIN b[248]
    DIRECTION OUTPUT ;
    USE SIGNAL ;
    PORT
      LAYER M4 ;
        RECT  25.836 42.192 25.92 42.216 ;
    END
  END b[248]
  PIN b[249]
    DIRECTION OUTPUT ;
    USE SIGNAL ;
    PORT
      LAYER M4 ;
        RECT  25.836 42.336 25.92 42.36 ;
    END
  END b[249]
  PIN b[24]
    DIRECTION OUTPUT ;
    USE SIGNAL ;
    PORT
      LAYER M4 ;
        RECT  25.836 4.176 25.92 4.2 ;
    END
  END b[24]
  PIN b[250]
    DIRECTION OUTPUT ;
    USE SIGNAL ;
    PORT
      LAYER M4 ;
        RECT  25.836 42.48 25.92 42.504 ;
    END
  END b[250]
  PIN b[251]
    DIRECTION OUTPUT ;
    USE SIGNAL ;
    PORT
      LAYER M4 ;
        RECT  25.836 42.624 25.92 42.648 ;
    END
  END b[251]
  PIN b[252]
    DIRECTION OUTPUT ;
    USE SIGNAL ;
    PORT
      LAYER M4 ;
        RECT  25.836 42.768 25.92 42.792 ;
    END
  END b[252]
  PIN b[253]
    DIRECTION OUTPUT ;
    USE SIGNAL ;
    PORT
      LAYER M4 ;
        RECT  25.836 42.912 25.92 42.936 ;
    END
  END b[253]
  PIN b[254]
    DIRECTION OUTPUT ;
    USE SIGNAL ;
    PORT
      LAYER M4 ;
        RECT  25.836 43.056 25.92 43.08 ;
    END
  END b[254]
  PIN b[255]
    DIRECTION OUTPUT ;
    USE SIGNAL ;
    PORT
      LAYER M4 ;
        RECT  25.836 43.2 25.92 43.224 ;
    END
  END b[255]
  PIN b[256]
    DIRECTION OUTPUT ;
    USE SIGNAL ;
    PORT
      LAYER M4 ;
        RECT  25.836 34.128 25.92 34.152 ;
    END
  END b[256]
  PIN b[257]
    DIRECTION OUTPUT ;
    USE SIGNAL ;
    PORT
      LAYER M4 ;
        RECT  25.836 34.272 25.92 34.296 ;
    END
  END b[257]
  PIN b[258]
    DIRECTION OUTPUT ;
    USE SIGNAL ;
    PORT
      LAYER M4 ;
        RECT  25.836 34.416 25.92 34.44 ;
    END
  END b[258]
  PIN b[259]
    DIRECTION OUTPUT ;
    USE SIGNAL ;
    PORT
      LAYER M4 ;
        RECT  25.836 34.56 25.92 34.584 ;
    END
  END b[259]
  PIN b[25]
    DIRECTION OUTPUT ;
    USE SIGNAL ;
    PORT
      LAYER M4 ;
        RECT  25.836 4.32 25.92 4.344 ;
    END
  END b[25]
  PIN b[260]
    DIRECTION OUTPUT ;
    USE SIGNAL ;
    PORT
      LAYER M4 ;
        RECT  25.836 34.704 25.92 34.728 ;
    END
  END b[260]
  PIN b[261]
    DIRECTION OUTPUT ;
    USE SIGNAL ;
    PORT
      LAYER M4 ;
        RECT  25.836 34.848 25.92 34.872 ;
    END
  END b[261]
  PIN b[262]
    DIRECTION OUTPUT ;
    USE SIGNAL ;
    PORT
      LAYER M4 ;
        RECT  25.836 34.992 25.92 35.016 ;
    END
  END b[262]
  PIN b[263]
    DIRECTION OUTPUT ;
    USE SIGNAL ;
    PORT
      LAYER M4 ;
        RECT  25.836 35.136 25.92 35.16 ;
    END
  END b[263]
  PIN b[264]
    DIRECTION OUTPUT ;
    USE SIGNAL ;
    PORT
      LAYER M4 ;
        RECT  25.836 35.28 25.92 35.304 ;
    END
  END b[264]
  PIN b[265]
    DIRECTION OUTPUT ;
    USE SIGNAL ;
    PORT
      LAYER M4 ;
        RECT  25.836 35.424 25.92 35.448 ;
    END
  END b[265]
  PIN b[266]
    DIRECTION OUTPUT ;
    USE SIGNAL ;
    PORT
      LAYER M4 ;
        RECT  25.836 35.568 25.92 35.592 ;
    END
  END b[266]
  PIN b[267]
    DIRECTION OUTPUT ;
    USE SIGNAL ;
    PORT
      LAYER M4 ;
        RECT  25.836 35.712 25.92 35.736 ;
    END
  END b[267]
  PIN b[268]
    DIRECTION OUTPUT ;
    USE SIGNAL ;
    PORT
      LAYER M4 ;
        RECT  25.836 35.856 25.92 35.88 ;
    END
  END b[268]
  PIN b[269]
    DIRECTION OUTPUT ;
    USE SIGNAL ;
    PORT
      LAYER M4 ;
        RECT  25.836 36 25.92 36.024 ;
    END
  END b[269]
  PIN b[26]
    DIRECTION OUTPUT ;
    USE SIGNAL ;
    PORT
      LAYER M4 ;
        RECT  25.836 4.464 25.92 4.488 ;
    END
  END b[26]
  PIN b[270]
    DIRECTION OUTPUT ;
    USE SIGNAL ;
    PORT
      LAYER M4 ;
        RECT  25.836 36.144 25.92 36.168 ;
    END
  END b[270]
  PIN b[271]
    DIRECTION OUTPUT ;
    USE SIGNAL ;
    PORT
      LAYER M4 ;
        RECT  25.836 36.288 25.92 36.312 ;
    END
  END b[271]
  PIN b[272]
    DIRECTION OUTPUT ;
    USE SIGNAL ;
    PORT
      LAYER M4 ;
        RECT  25.836 36.432 25.92 36.456 ;
    END
  END b[272]
  PIN b[273]
    DIRECTION OUTPUT ;
    USE SIGNAL ;
    PORT
      LAYER M4 ;
        RECT  25.836 36.576 25.92 36.6 ;
    END
  END b[273]
  PIN b[274]
    DIRECTION OUTPUT ;
    USE SIGNAL ;
    PORT
      LAYER M4 ;
        RECT  25.836 36.72 25.92 36.744 ;
    END
  END b[274]
  PIN b[275]
    DIRECTION OUTPUT ;
    USE SIGNAL ;
    PORT
      LAYER M4 ;
        RECT  25.836 36.864 25.92 36.888 ;
    END
  END b[275]
  PIN b[276]
    DIRECTION OUTPUT ;
    USE SIGNAL ;
    PORT
      LAYER M4 ;
        RECT  25.836 37.008 25.92 37.032 ;
    END
  END b[276]
  PIN b[277]
    DIRECTION OUTPUT ;
    USE SIGNAL ;
    PORT
      LAYER M4 ;
        RECT  25.836 37.152 25.92 37.176 ;
    END
  END b[277]
  PIN b[278]
    DIRECTION OUTPUT ;
    USE SIGNAL ;
    PORT
      LAYER M4 ;
        RECT  25.836 37.296 25.92 37.32 ;
    END
  END b[278]
  PIN b[279]
    DIRECTION OUTPUT ;
    USE SIGNAL ;
    PORT
      LAYER M4 ;
        RECT  25.836 37.44 25.92 37.464 ;
    END
  END b[279]
  PIN b[27]
    DIRECTION OUTPUT ;
    USE SIGNAL ;
    PORT
      LAYER M4 ;
        RECT  25.836 4.608 25.92 4.632 ;
    END
  END b[27]
  PIN b[280]
    DIRECTION OUTPUT ;
    USE SIGNAL ;
    PORT
      LAYER M4 ;
        RECT  25.836 37.584 25.92 37.608 ;
    END
  END b[280]
  PIN b[281]
    DIRECTION OUTPUT ;
    USE SIGNAL ;
    PORT
      LAYER M4 ;
        RECT  25.836 37.728 25.92 37.752 ;
    END
  END b[281]
  PIN b[282]
    DIRECTION OUTPUT ;
    USE SIGNAL ;
    PORT
      LAYER M4 ;
        RECT  25.836 37.872 25.92 37.896 ;
    END
  END b[282]
  PIN b[283]
    DIRECTION OUTPUT ;
    USE SIGNAL ;
    PORT
      LAYER M4 ;
        RECT  25.836 38.016 25.92 38.04 ;
    END
  END b[283]
  PIN b[284]
    DIRECTION OUTPUT ;
    USE SIGNAL ;
    PORT
      LAYER M4 ;
        RECT  25.836 38.16 25.92 38.184 ;
    END
  END b[284]
  PIN b[285]
    DIRECTION OUTPUT ;
    USE SIGNAL ;
    PORT
      LAYER M4 ;
        RECT  25.836 38.304 25.92 38.328 ;
    END
  END b[285]
  PIN b[286]
    DIRECTION OUTPUT ;
    USE SIGNAL ;
    PORT
      LAYER M4 ;
        RECT  25.836 38.448 25.92 38.472 ;
    END
  END b[286]
  PIN b[287]
    DIRECTION OUTPUT ;
    USE SIGNAL ;
    PORT
      LAYER M4 ;
        RECT  25.836 38.592 25.92 38.616 ;
    END
  END b[287]
  PIN b[288]
    DIRECTION OUTPUT ;
    USE SIGNAL ;
    PORT
      LAYER M4 ;
        RECT  25.836 28.368 25.92 28.392 ;
    END
  END b[288]
  PIN b[289]
    DIRECTION OUTPUT ;
    USE SIGNAL ;
    PORT
      LAYER M4 ;
        RECT  25.836 28.512 25.92 28.536 ;
    END
  END b[289]
  PIN b[28]
    DIRECTION OUTPUT ;
    USE SIGNAL ;
    PORT
      LAYER M4 ;
        RECT  25.836 4.752 25.92 4.776 ;
    END
  END b[28]
  PIN b[290]
    DIRECTION OUTPUT ;
    USE SIGNAL ;
    PORT
      LAYER M4 ;
        RECT  25.836 28.656 25.92 28.68 ;
    END
  END b[290]
  PIN b[291]
    DIRECTION OUTPUT ;
    USE SIGNAL ;
    PORT
      LAYER M4 ;
        RECT  25.836 28.8 25.92 28.824 ;
    END
  END b[291]
  PIN b[292]
    DIRECTION OUTPUT ;
    USE SIGNAL ;
    PORT
      LAYER M4 ;
        RECT  25.836 28.944 25.92 28.968 ;
    END
  END b[292]
  PIN b[293]
    DIRECTION OUTPUT ;
    USE SIGNAL ;
    PORT
      LAYER M4 ;
        RECT  25.836 29.088 25.92 29.112 ;
    END
  END b[293]
  PIN b[294]
    DIRECTION OUTPUT ;
    USE SIGNAL ;
    PORT
      LAYER M4 ;
        RECT  25.836 29.232 25.92 29.256 ;
    END
  END b[294]
  PIN b[295]
    DIRECTION OUTPUT ;
    USE SIGNAL ;
    PORT
      LAYER M4 ;
        RECT  25.836 29.376 25.92 29.4 ;
    END
  END b[295]
  PIN b[29]
    DIRECTION OUTPUT ;
    USE SIGNAL ;
    PORT
      LAYER M4 ;
        RECT  25.836 4.896 25.92 4.92 ;
    END
  END b[29]
  PIN b[2]
    DIRECTION OUTPUT ;
    USE SIGNAL ;
    PORT
      LAYER M4 ;
        RECT  25.836 1.008 25.92 1.032 ;
    END
  END b[2]
  PIN b[30]
    DIRECTION OUTPUT ;
    USE SIGNAL ;
    PORT
      LAYER M4 ;
        RECT  25.836 5.04 25.92 5.064 ;
    END
  END b[30]
  PIN b[31]
    DIRECTION OUTPUT ;
    USE SIGNAL ;
    PORT
      LAYER M4 ;
        RECT  25.836 5.184 25.92 5.208 ;
    END
  END b[31]
  PIN b[32]
    DIRECTION OUTPUT ;
    USE SIGNAL ;
    PORT
      LAYER M4 ;
        RECT  25.836 5.328 25.92 5.352 ;
    END
  END b[32]
  PIN b[33]
    DIRECTION OUTPUT ;
    USE SIGNAL ;
    PORT
      LAYER M4 ;
        RECT  25.836 5.472 25.92 5.496 ;
    END
  END b[33]
  PIN b[34]
    DIRECTION OUTPUT ;
    USE SIGNAL ;
    PORT
      LAYER M4 ;
        RECT  25.836 5.616 25.92 5.64 ;
    END
  END b[34]
  PIN b[35]
    DIRECTION OUTPUT ;
    USE SIGNAL ;
    PORT
      LAYER M4 ;
        RECT  25.836 5.76 25.92 5.784 ;
    END
  END b[35]
  PIN b[36]
    DIRECTION OUTPUT ;
    USE SIGNAL ;
    PORT
      LAYER M4 ;
        RECT  25.836 5.904 25.92 5.928 ;
    END
  END b[36]
  PIN b[37]
    DIRECTION OUTPUT ;
    USE SIGNAL ;
    PORT
      LAYER M4 ;
        RECT  25.836 6.048 25.92 6.072 ;
    END
  END b[37]
  PIN b[38]
    DIRECTION OUTPUT ;
    USE SIGNAL ;
    PORT
      LAYER M4 ;
        RECT  25.836 6.192 25.92 6.216 ;
    END
  END b[38]
  PIN b[39]
    DIRECTION OUTPUT ;
    USE SIGNAL ;
    PORT
      LAYER M4 ;
        RECT  25.836 6.336 25.92 6.36 ;
    END
  END b[39]
  PIN b[3]
    DIRECTION OUTPUT ;
    USE SIGNAL ;
    PORT
      LAYER M4 ;
        RECT  25.836 1.152 25.92 1.176 ;
    END
  END b[3]
  PIN b[40]
    DIRECTION OUTPUT ;
    USE SIGNAL ;
    PORT
      LAYER M4 ;
        RECT  25.836 6.48 25.92 6.504 ;
    END
  END b[40]
  PIN b[41]
    DIRECTION OUTPUT ;
    USE SIGNAL ;
    PORT
      LAYER M4 ;
        RECT  25.836 6.624 25.92 6.648 ;
    END
  END b[41]
  PIN b[42]
    DIRECTION OUTPUT ;
    USE SIGNAL ;
    PORT
      LAYER M4 ;
        RECT  25.836 6.768 25.92 6.792 ;
    END
  END b[42]
  PIN b[43]
    DIRECTION OUTPUT ;
    USE SIGNAL ;
    PORT
      LAYER M4 ;
        RECT  25.836 6.912 25.92 6.936 ;
    END
  END b[43]
  PIN b[44]
    DIRECTION OUTPUT ;
    USE SIGNAL ;
    PORT
      LAYER M4 ;
        RECT  25.836 7.056 25.92 7.08 ;
    END
  END b[44]
  PIN b[45]
    DIRECTION OUTPUT ;
    USE SIGNAL ;
    PORT
      LAYER M4 ;
        RECT  25.836 7.2 25.92 7.224 ;
    END
  END b[45]
  PIN b[46]
    DIRECTION OUTPUT ;
    USE SIGNAL ;
    PORT
      LAYER M4 ;
        RECT  25.836 7.344 25.92 7.368 ;
    END
  END b[46]
  PIN b[47]
    DIRECTION OUTPUT ;
    USE SIGNAL ;
    PORT
      LAYER M4 ;
        RECT  25.836 7.488 25.92 7.512 ;
    END
  END b[47]
  PIN b[48]
    DIRECTION OUTPUT ;
    USE SIGNAL ;
    PORT
      LAYER M4 ;
        RECT  25.836 7.632 25.92 7.656 ;
    END
  END b[48]
  PIN b[49]
    DIRECTION OUTPUT ;
    USE SIGNAL ;
    PORT
      LAYER M4 ;
        RECT  25.836 7.776 25.92 7.8 ;
    END
  END b[49]
  PIN b[4]
    DIRECTION OUTPUT ;
    USE SIGNAL ;
    PORT
      LAYER M4 ;
        RECT  25.836 1.296 25.92 1.32 ;
    END
  END b[4]
  PIN b[50]
    DIRECTION OUTPUT ;
    USE SIGNAL ;
    PORT
      LAYER M4 ;
        RECT  25.836 7.92 25.92 7.944 ;
    END
  END b[50]
  PIN b[51]
    DIRECTION OUTPUT ;
    USE SIGNAL ;
    PORT
      LAYER M4 ;
        RECT  25.836 8.064 25.92 8.088 ;
    END
  END b[51]
  PIN b[52]
    DIRECTION OUTPUT ;
    USE SIGNAL ;
    PORT
      LAYER M4 ;
        RECT  25.836 8.208 25.92 8.232 ;
    END
  END b[52]
  PIN b[53]
    DIRECTION OUTPUT ;
    USE SIGNAL ;
    PORT
      LAYER M4 ;
        RECT  25.836 8.352 25.92 8.376 ;
    END
  END b[53]
  PIN b[54]
    DIRECTION OUTPUT ;
    USE SIGNAL ;
    PORT
      LAYER M4 ;
        RECT  25.836 8.496 25.92 8.52 ;
    END
  END b[54]
  PIN b[55]
    DIRECTION OUTPUT ;
    USE SIGNAL ;
    PORT
      LAYER M4 ;
        RECT  25.836 8.64 25.92 8.664 ;
    END
  END b[55]
  PIN b[56]
    DIRECTION OUTPUT ;
    USE SIGNAL ;
    PORT
      LAYER M4 ;
        RECT  25.836 8.784 25.92 8.808 ;
    END
  END b[56]
  PIN b[57]
    DIRECTION OUTPUT ;
    USE SIGNAL ;
    PORT
      LAYER M4 ;
        RECT  25.836 8.928 25.92 8.952 ;
    END
  END b[57]
  PIN b[58]
    DIRECTION OUTPUT ;
    USE SIGNAL ;
    PORT
      LAYER M4 ;
        RECT  25.836 9.072 25.92 9.096 ;
    END
  END b[58]
  PIN b[59]
    DIRECTION OUTPUT ;
    USE SIGNAL ;
    PORT
      LAYER M4 ;
        RECT  25.836 9.216 25.92 9.24 ;
    END
  END b[59]
  PIN b[5]
    DIRECTION OUTPUT ;
    USE SIGNAL ;
    PORT
      LAYER M4 ;
        RECT  25.836 1.44 25.92 1.464 ;
    END
  END b[5]
  PIN b[60]
    DIRECTION OUTPUT ;
    USE SIGNAL ;
    PORT
      LAYER M4 ;
        RECT  25.836 9.36 25.92 9.384 ;
    END
  END b[60]
  PIN b[61]
    DIRECTION OUTPUT ;
    USE SIGNAL ;
    PORT
      LAYER M4 ;
        RECT  25.836 9.504 25.92 9.528 ;
    END
  END b[61]
  PIN b[62]
    DIRECTION OUTPUT ;
    USE SIGNAL ;
    PORT
      LAYER M4 ;
        RECT  25.836 9.648 25.92 9.672 ;
    END
  END b[62]
  PIN b[63]
    DIRECTION OUTPUT ;
    USE SIGNAL ;
    PORT
      LAYER M4 ;
        RECT  25.836 9.792 25.92 9.816 ;
    END
  END b[63]
  PIN b[64]
    DIRECTION OUTPUT ;
    USE SIGNAL ;
    PORT
      LAYER M4 ;
        RECT  25.836 23.76 25.92 23.784 ;
    END
  END b[64]
  PIN b[65]
    DIRECTION OUTPUT ;
    USE SIGNAL ;
    PORT
      LAYER M4 ;
        RECT  25.836 23.904 25.92 23.928 ;
    END
  END b[65]
  PIN b[66]
    DIRECTION OUTPUT ;
    USE SIGNAL ;
    PORT
      LAYER M4 ;
        RECT  25.836 24.048 25.92 24.072 ;
    END
  END b[66]
  PIN b[67]
    DIRECTION OUTPUT ;
    USE SIGNAL ;
    PORT
      LAYER M4 ;
        RECT  25.836 24.192 25.92 24.216 ;
    END
  END b[67]
  PIN b[68]
    DIRECTION OUTPUT ;
    USE SIGNAL ;
    PORT
      LAYER M4 ;
        RECT  25.836 24.336 25.92 24.36 ;
    END
  END b[68]
  PIN b[69]
    DIRECTION OUTPUT ;
    USE SIGNAL ;
    PORT
      LAYER M4 ;
        RECT  25.836 24.48 25.92 24.504 ;
    END
  END b[69]
  PIN b[6]
    DIRECTION OUTPUT ;
    USE SIGNAL ;
    PORT
      LAYER M4 ;
        RECT  25.836 1.584 25.92 1.608 ;
    END
  END b[6]
  PIN b[70]
    DIRECTION OUTPUT ;
    USE SIGNAL ;
    PORT
      LAYER M4 ;
        RECT  25.836 24.624 25.92 24.648 ;
    END
  END b[70]
  PIN b[71]
    DIRECTION OUTPUT ;
    USE SIGNAL ;
    PORT
      LAYER M4 ;
        RECT  25.836 24.768 25.92 24.792 ;
    END
  END b[71]
  PIN b[72]
    DIRECTION OUTPUT ;
    USE SIGNAL ;
    PORT
      LAYER M4 ;
        RECT  25.836 24.912 25.92 24.936 ;
    END
  END b[72]
  PIN b[73]
    DIRECTION OUTPUT ;
    USE SIGNAL ;
    PORT
      LAYER M4 ;
        RECT  25.836 25.056 25.92 25.08 ;
    END
  END b[73]
  PIN b[74]
    DIRECTION OUTPUT ;
    USE SIGNAL ;
    PORT
      LAYER M4 ;
        RECT  25.836 25.2 25.92 25.224 ;
    END
  END b[74]
  PIN b[75]
    DIRECTION OUTPUT ;
    USE SIGNAL ;
    PORT
      LAYER M4 ;
        RECT  25.836 25.344 25.92 25.368 ;
    END
  END b[75]
  PIN b[76]
    DIRECTION OUTPUT ;
    USE SIGNAL ;
    PORT
      LAYER M4 ;
        RECT  25.836 25.488 25.92 25.512 ;
    END
  END b[76]
  PIN b[77]
    DIRECTION OUTPUT ;
    USE SIGNAL ;
    PORT
      LAYER M4 ;
        RECT  25.836 25.632 25.92 25.656 ;
    END
  END b[77]
  PIN b[78]
    DIRECTION OUTPUT ;
    USE SIGNAL ;
    PORT
      LAYER M4 ;
        RECT  25.836 25.776 25.92 25.8 ;
    END
  END b[78]
  PIN b[79]
    DIRECTION OUTPUT ;
    USE SIGNAL ;
    PORT
      LAYER M4 ;
        RECT  25.836 25.92 25.92 25.944 ;
    END
  END b[79]
  PIN b[7]
    DIRECTION OUTPUT ;
    USE SIGNAL ;
    PORT
      LAYER M4 ;
        RECT  25.836 1.728 25.92 1.752 ;
    END
  END b[7]
  PIN b[80]
    DIRECTION OUTPUT ;
    USE SIGNAL ;
    PORT
      LAYER M4 ;
        RECT  25.836 26.064 25.92 26.088 ;
    END
  END b[80]
  PIN b[81]
    DIRECTION OUTPUT ;
    USE SIGNAL ;
    PORT
      LAYER M4 ;
        RECT  25.836 26.208 25.92 26.232 ;
    END
  END b[81]
  PIN b[82]
    DIRECTION OUTPUT ;
    USE SIGNAL ;
    PORT
      LAYER M4 ;
        RECT  25.836 26.352 25.92 26.376 ;
    END
  END b[82]
  PIN b[83]
    DIRECTION OUTPUT ;
    USE SIGNAL ;
    PORT
      LAYER M4 ;
        RECT  25.836 26.496 25.92 26.52 ;
    END
  END b[83]
  PIN b[84]
    DIRECTION OUTPUT ;
    USE SIGNAL ;
    PORT
      LAYER M4 ;
        RECT  25.836 26.64 25.92 26.664 ;
    END
  END b[84]
  PIN b[85]
    DIRECTION OUTPUT ;
    USE SIGNAL ;
    PORT
      LAYER M4 ;
        RECT  25.836 26.784 25.92 26.808 ;
    END
  END b[85]
  PIN b[86]
    DIRECTION OUTPUT ;
    USE SIGNAL ;
    PORT
      LAYER M4 ;
        RECT  25.836 26.928 25.92 26.952 ;
    END
  END b[86]
  PIN b[87]
    DIRECTION OUTPUT ;
    USE SIGNAL ;
    PORT
      LAYER M4 ;
        RECT  25.836 27.072 25.92 27.096 ;
    END
  END b[87]
  PIN b[88]
    DIRECTION OUTPUT ;
    USE SIGNAL ;
    PORT
      LAYER M4 ;
        RECT  25.836 27.216 25.92 27.24 ;
    END
  END b[88]
  PIN b[89]
    DIRECTION OUTPUT ;
    USE SIGNAL ;
    PORT
      LAYER M4 ;
        RECT  25.836 27.36 25.92 27.384 ;
    END
  END b[89]
  PIN b[8]
    DIRECTION OUTPUT ;
    USE SIGNAL ;
    PORT
      LAYER M4 ;
        RECT  25.836 1.872 25.92 1.896 ;
    END
  END b[8]
  PIN b[90]
    DIRECTION OUTPUT ;
    USE SIGNAL ;
    PORT
      LAYER M4 ;
        RECT  25.836 27.504 25.92 27.528 ;
    END
  END b[90]
  PIN b[91]
    DIRECTION OUTPUT ;
    USE SIGNAL ;
    PORT
      LAYER M4 ;
        RECT  25.836 27.648 25.92 27.672 ;
    END
  END b[91]
  PIN b[92]
    DIRECTION OUTPUT ;
    USE SIGNAL ;
    PORT
      LAYER M4 ;
        RECT  25.836 27.792 25.92 27.816 ;
    END
  END b[92]
  PIN b[93]
    DIRECTION OUTPUT ;
    USE SIGNAL ;
    PORT
      LAYER M4 ;
        RECT  25.836 27.936 25.92 27.96 ;
    END
  END b[93]
  PIN b[94]
    DIRECTION OUTPUT ;
    USE SIGNAL ;
    PORT
      LAYER M4 ;
        RECT  25.836 28.08 25.92 28.104 ;
    END
  END b[94]
  PIN b[95]
    DIRECTION OUTPUT ;
    USE SIGNAL ;
    PORT
      LAYER M4 ;
        RECT  25.836 28.224 25.92 28.248 ;
    END
  END b[95]
  PIN b[96]
    DIRECTION OUTPUT ;
    USE SIGNAL ;
    PORT
      LAYER M4 ;
        RECT  25.836 9.936 25.92 9.96 ;
    END
  END b[96]
  PIN b[97]
    DIRECTION OUTPUT ;
    USE SIGNAL ;
    PORT
      LAYER M4 ;
        RECT  25.836 10.08 25.92 10.104 ;
    END
  END b[97]
  PIN b[98]
    DIRECTION OUTPUT ;
    USE SIGNAL ;
    PORT
      LAYER M4 ;
        RECT  25.836 10.224 25.92 10.248 ;
    END
  END b[98]
  PIN b[99]
    DIRECTION OUTPUT ;
    USE SIGNAL ;
    PORT
      LAYER M4 ;
        RECT  25.836 10.368 25.92 10.392 ;
    END
  END b[99]
  PIN b[9]
    DIRECTION OUTPUT ;
    USE SIGNAL ;
    PORT
      LAYER M4 ;
        RECT  25.836 2.016 25.92 2.04 ;
    END
  END b[9]
  PIN ck
    DIRECTION INPUT ;
    USE SIGNAL ;
    PORT
      LAYER M5 ;
        RECT  5.328 0 5.352 0.084 ;
    END
  END ck
  PIN rst_n
    DIRECTION INPUT ;
    USE SIGNAL ;
    PORT
      LAYER M5 ;
        RECT  5.472 0 5.496 0.084 ;
    END
  END rst_n
  PIN VDD
    DIRECTION INOUT ;
    USE POWER ;
    PORT
      LAYER M5 ;
        RECT  21.492 2.151 21.612 49.689 ;
        RECT  18.792 2.151 18.912 49.689 ;
        RECT  16.092 2.151 16.212 49.689 ;
        RECT  13.392 2.151 13.512 49.689 ;
        RECT  10.692 2.151 10.812 49.689 ;
        RECT  7.992 2.151 8.112 49.689 ;
        RECT  5.292 2.151 5.412 49.689 ;
        RECT  2.592 2.151 2.712 49.689 ;
    END
  END VDD
  PIN VSS
    DIRECTION INOUT ;
    USE GROUND ;
    PORT
      LAYER M5 ;
        RECT  21.3 2.137 21.42 49.703 ;
        RECT  18.6 2.137 18.72 49.703 ;
        RECT  15.9 2.137 16.02 49.703 ;
        RECT  13.2 2.137 13.32 49.703 ;
        RECT  10.5 2.137 10.62 49.703 ;
        RECT  7.8 2.137 7.92 49.703 ;
        RECT  5.1 2.137 5.22 49.703 ;
        RECT  2.4 2.137 2.52 49.703 ;
    END
  END VSS
  OBS
    LAYER RVTN ;
     RECT  2.16 2.16 23.76 2.295 ;
     RECT  2.16 2.565 23.76 2.835 ;
     RECT  2.16 3.105 23.76 3.375 ;
     RECT  2.16 3.645 23.76 3.915 ;
     RECT  2.16 4.185 23.76 4.455 ;
     RECT  2.16 4.725 23.76 4.995 ;
     RECT  2.16 5.265 23.76 5.535 ;
     RECT  2.16 5.805 23.76 6.075 ;
     RECT  2.16 6.345 23.76 6.615 ;
     RECT  2.16 6.885 23.76 7.155 ;
     RECT  2.16 7.425 23.76 7.695 ;
     RECT  2.16 7.965 23.76 8.235 ;
     RECT  2.16 8.505 23.76 8.775 ;
     RECT  2.16 9.045 23.76 9.315 ;
     RECT  2.16 9.585 23.76 9.855 ;
     RECT  2.16 10.125 23.76 10.395 ;
     RECT  2.16 10.665 23.76 10.935 ;
     RECT  2.16 11.205 23.76 11.475 ;
     RECT  2.16 11.745 23.76 12.015 ;
     RECT  2.16 12.285 23.76 12.555 ;
     RECT  2.16 12.825 23.76 13.095 ;
     RECT  2.16 13.365 23.76 13.635 ;
     RECT  2.16 13.905 23.76 14.175 ;
     RECT  2.16 14.445 23.76 14.715 ;
     RECT  2.16 14.985 23.76 15.255 ;
     RECT  2.16 15.525 23.76 15.795 ;
     RECT  2.16 16.065 23.76 16.335 ;
     RECT  2.16 16.605 23.76 16.875 ;
     RECT  2.16 17.145 23.76 17.415 ;
     RECT  2.16 17.685 23.76 17.955 ;
     RECT  2.16 18.225 23.76 18.495 ;
     RECT  2.16 18.765 23.76 19.035 ;
     RECT  2.16 19.305 23.76 19.575 ;
     RECT  2.16 19.845 23.76 20.115 ;
     RECT  2.16 20.385 23.76 20.655 ;
     RECT  2.16 20.925 23.76 21.195 ;
     RECT  2.16 21.465 23.76 21.735 ;
     RECT  2.16 22.005 23.76 22.275 ;
     RECT  2.16 22.545 23.76 22.815 ;
     RECT  2.16 23.085 23.76 23.355 ;
     RECT  2.16 23.625 23.76 23.895 ;
     RECT  2.16 24.165 23.76 24.435 ;
     RECT  2.16 24.705 23.76 24.975 ;
     RECT  2.16 25.245 23.76 25.515 ;
     RECT  2.16 25.785 23.76 26.055 ;
     RECT  2.16 26.325 23.76 26.595 ;
     RECT  2.16 26.865 23.76 27.135 ;
     RECT  2.16 27.405 23.76 27.675 ;
     RECT  2.16 27.945 23.76 28.215 ;
     RECT  2.16 28.485 23.76 28.755 ;
     RECT  2.16 29.025 23.76 29.295 ;
     RECT  2.16 29.565 23.76 29.835 ;
     RECT  2.16 30.105 23.76 30.375 ;
     RECT  2.16 30.645 23.76 30.915 ;
     RECT  2.16 31.185 23.76 31.455 ;
     RECT  2.16 31.725 23.76 31.995 ;
     RECT  2.16 32.265 23.76 32.535 ;
     RECT  2.16 32.805 23.76 33.075 ;
     RECT  2.16 33.345 23.76 33.615 ;
     RECT  2.16 33.885 23.76 34.155 ;
     RECT  2.16 34.425 23.76 34.695 ;
     RECT  2.16 34.965 23.76 35.235 ;
     RECT  2.16 35.505 23.76 35.775 ;
     RECT  2.16 36.045 23.76 36.315 ;
     RECT  2.16 36.585 23.76 36.855 ;
     RECT  2.16 37.125 23.76 37.395 ;
     RECT  2.16 37.665 23.76 37.935 ;
     RECT  2.16 38.205 23.76 38.475 ;
     RECT  2.16 38.745 23.76 39.015 ;
     RECT  2.16 39.285 23.76 39.555 ;
     RECT  2.16 39.825 23.76 40.095 ;
     RECT  2.16 40.365 23.76 40.635 ;
     RECT  2.16 40.905 23.76 41.175 ;
     RECT  2.16 41.445 23.76 41.715 ;
     RECT  2.16 41.985 23.76 42.255 ;
     RECT  2.16 42.525 23.76 42.795 ;
     RECT  2.16 43.065 23.76 43.335 ;
     RECT  2.16 43.605 23.76 43.875 ;
     RECT  2.16 44.145 23.76 44.415 ;
     RECT  2.16 44.685 23.76 44.955 ;
     RECT  2.16 45.225 23.76 45.495 ;
     RECT  2.16 45.765 23.76 46.035 ;
     RECT  2.16 46.305 23.76 46.575 ;
     RECT  2.16 46.845 23.76 47.115 ;
     RECT  2.16 47.385 23.76 47.655 ;
     RECT  2.16 47.925 23.76 48.195 ;
     RECT  2.16 48.465 23.76 48.735 ;
     RECT  2.16 49.005 23.76 49.275 ;
     RECT  2.16 49.545 23.76 49.68 ;
    LAYER RVTP ;
     RECT  2.16 2.295 23.76 2.565 ;
     RECT  2.16 2.835 23.76 3.105 ;
     RECT  2.16 3.375 23.76 3.645 ;
     RECT  2.16 3.915 23.76 4.185 ;
     RECT  2.16 4.455 23.76 4.725 ;
     RECT  2.16 4.995 23.76 5.265 ;
     RECT  2.16 5.535 23.76 5.805 ;
     RECT  2.16 6.075 23.76 6.345 ;
     RECT  2.16 6.615 23.76 6.885 ;
     RECT  2.16 7.155 23.76 7.425 ;
     RECT  2.16 7.695 23.76 7.965 ;
     RECT  2.16 8.235 23.76 8.505 ;
     RECT  2.16 8.775 23.76 9.045 ;
     RECT  2.16 9.315 23.76 9.585 ;
     RECT  2.16 9.855 23.76 10.125 ;
     RECT  2.16 10.395 23.76 10.665 ;
     RECT  2.16 10.935 23.76 11.205 ;
     RECT  2.16 11.475 23.76 11.745 ;
     RECT  2.16 12.015 23.76 12.285 ;
     RECT  2.16 12.555 23.76 12.825 ;
     RECT  2.16 13.095 23.76 13.365 ;
     RECT  2.16 13.635 23.76 13.905 ;
     RECT  2.16 14.175 23.76 14.445 ;
     RECT  2.16 14.715 23.76 14.985 ;
     RECT  2.16 15.255 23.76 15.525 ;
     RECT  2.16 15.795 23.76 16.065 ;
     RECT  2.16 16.335 23.76 16.605 ;
     RECT  2.16 16.875 23.76 17.145 ;
     RECT  2.16 17.415 23.76 17.685 ;
     RECT  2.16 17.955 23.76 18.225 ;
     RECT  2.16 18.495 23.76 18.765 ;
     RECT  2.16 19.035 23.76 19.305 ;
     RECT  2.16 19.575 23.76 19.845 ;
     RECT  2.16 20.115 23.76 20.385 ;
     RECT  2.16 20.655 23.76 20.925 ;
     RECT  2.16 21.195 23.76 21.465 ;
     RECT  2.16 21.735 23.76 22.005 ;
     RECT  2.16 22.275 23.76 22.545 ;
     RECT  2.16 22.815 23.76 23.085 ;
     RECT  2.16 23.355 23.76 23.625 ;
     RECT  2.16 23.895 23.76 24.165 ;
     RECT  2.16 24.435 23.76 24.705 ;
     RECT  2.16 24.975 23.76 25.245 ;
     RECT  2.16 25.515 23.76 25.785 ;
     RECT  2.16 26.055 23.76 26.325 ;
     RECT  2.16 26.595 23.76 26.865 ;
     RECT  2.16 27.135 23.76 27.405 ;
     RECT  2.16 27.675 23.76 27.945 ;
     RECT  2.16 28.215 23.76 28.485 ;
     RECT  2.16 28.755 23.76 29.025 ;
     RECT  2.16 29.295 23.76 29.565 ;
     RECT  2.16 29.835 23.76 30.105 ;
     RECT  2.16 30.375 23.76 30.645 ;
     RECT  2.16 30.915 23.76 31.185 ;
     RECT  2.16 31.455 23.76 31.725 ;
     RECT  2.16 31.995 23.76 32.265 ;
     RECT  2.16 32.535 23.76 32.805 ;
     RECT  2.16 33.075 23.76 33.345 ;
     RECT  2.16 33.615 23.76 33.885 ;
     RECT  2.16 34.155 23.76 34.425 ;
     RECT  2.16 34.695 23.76 34.965 ;
     RECT  2.16 35.235 23.76 35.505 ;
     RECT  2.16 35.775 23.76 36.045 ;
     RECT  2.16 36.315 23.76 36.585 ;
     RECT  2.16 36.855 23.76 37.125 ;
     RECT  2.16 37.395 23.76 37.665 ;
     RECT  2.16 37.935 23.76 38.205 ;
     RECT  2.16 38.475 23.76 38.745 ;
     RECT  2.16 39.015 23.76 39.285 ;
     RECT  2.16 39.555 23.76 39.825 ;
     RECT  2.16 40.095 23.76 40.365 ;
     RECT  2.16 40.635 23.76 40.905 ;
     RECT  2.16 41.175 23.76 41.445 ;
     RECT  2.16 41.715 23.76 41.985 ;
     RECT  2.16 42.255 23.76 42.525 ;
     RECT  2.16 42.795 23.76 43.065 ;
     RECT  2.16 43.335 23.76 43.605 ;
     RECT  2.16 43.875 23.76 44.145 ;
     RECT  2.16 44.415 23.76 44.685 ;
     RECT  2.16 44.955 23.76 45.225 ;
     RECT  2.16 45.495 23.76 45.765 ;
     RECT  2.16 46.035 23.76 46.305 ;
     RECT  2.16 46.575 23.76 46.845 ;
     RECT  2.16 47.115 23.76 47.385 ;
     RECT  2.16 47.655 23.76 47.925 ;
     RECT  2.16 48.195 23.76 48.465 ;
     RECT  2.16 48.735 23.76 49.005 ;
     RECT  2.16 49.275 23.76 49.545 ;
    LAYER M1 ;
     RECT  2.16 2.151 23.76 49.689 ;
    LAYER M2 ;
     RECT  0.103 13.032 0.499 13.05 ;
     RECT  0.499 12.492 0.535 13.05 ;
     RECT  0.499 48.438 0.535 48.456 ;
     RECT  0.535 12.222 2.16 13.05 ;
     RECT  0.535 14.22 2.16 14.778 ;
     RECT  0.103 17.082 2.16 17.1 ;
     RECT  0.535 22.626 2.16 23.922 ;
     RECT  0.535 42.732 2.16 42.75 ;
     RECT  0.103 44.496 2.16 44.514 ;
     RECT  0.535 47.862 2.16 48.456 ;
     RECT  2.16 2.151 8.527 49.689 ;
     RECT  8.527 2.151 9.347 49.734 ;
     RECT  9.347 2.151 23.76 49.689 ;
     RECT  23.76 14.526 23.963 34.218 ;
     RECT  23.76 39.024 23.963 39.618 ;
     RECT  23.963 15.696 24.323 34.218 ;
     RECT  24.323 15.768 24.359 34.218 ;
     RECT  23.76 6.516 24.503 10.08 ;
     RECT  24.359 17.226 24.503 34.218 ;
     RECT  23.76 2.808 24.539 2.826 ;
     RECT  24.503 18.126 24.539 34.218 ;
     RECT  23.963 39.6 24.539 39.618 ;
     RECT  24.539 18.126 24.755 29.394 ;
     RECT  23.76 44.316 24.791 44.334 ;
     RECT  24.755 28.224 24.827 29.394 ;
     RECT  23.963 14.526 24.863 14.544 ;
     RECT  24.359 15.768 24.863 16.434 ;
     RECT  24.539 30.384 24.899 34.218 ;
     RECT  24.899 33.894 24.935 34.218 ;
     RECT  24.899 30.384 24.971 32.724 ;
     RECT  24.755 18.126 25.007 27.324 ;
     RECT  23.76 5.706 25.043 5.724 ;
     RECT  24.503 6.516 25.043 7.956 ;
     RECT  24.503 17.226 25.043 17.244 ;
     RECT  25.007 18.126 25.043 24.966 ;
     RECT  24.503 9.126 25.079 10.08 ;
     RECT  25.043 7.056 25.115 7.956 ;
     RECT  25.043 18.576 25.115 18.594 ;
     RECT  25.043 20.394 25.115 24.966 ;
     RECT  24.827 28.224 25.115 29.25 ;
     RECT  24.971 30.384 25.115 31.212 ;
     RECT  24.971 32.076 25.115 32.724 ;
     RECT  24.935 33.894 25.115 33.912 ;
     RECT  23.76 42.462 25.115 42.48 ;
     RECT  25.115 7.056 25.151 7.722 ;
     RECT  25.115 30.456 25.151 31.212 ;
     RECT  25.115 32.076 25.151 32.094 ;
     RECT  25.115 20.394 25.439 21.654 ;
     RECT  25.115 22.824 25.439 24.966 ;
     RECT  25.007 25.794 25.547 27.324 ;
     RECT  25.439 22.896 25.583 24.966 ;
     RECT  25.547 26.1 25.619 27.324 ;
     RECT  25.583 24.912 25.655 24.966 ;
     RECT  25.115 29.07 25.655 29.169 ;
     RECT  25.439 20.394 25.691 21.114 ;
     RECT  25.583 22.896 25.691 24.12 ;
     RECT  25.655 24.912 25.727 24.93 ;
     RECT  25.691 20.394 25.763 21.069 ;
     RECT  25.655 29.151 25.763 29.169 ;
     RECT  25.151 30.618 25.763 31.212 ;
     RECT  25.627 36.558 25.763 36.576 ;
     RECT  25.079 9.126 25.771 10.044 ;
     RECT  24.863 16.344 25.771 16.434 ;
     RECT  25.771 9.054 25.799 10.044 ;
     RECT  25.619 26.568 25.799 27.324 ;
     RECT  25.763 31.194 25.799 31.212 ;
     RECT  25.151 7.056 25.835 7.074 ;
     RECT  25.799 9.054 25.835 9.81 ;
     RECT  25.771 16.344 25.835 17.172 ;
     RECT  25.763 20.394 25.835 20.412 ;
     RECT  25.691 23.328 25.835 24.039 ;
     RECT  25.115 28.224 25.835 28.242 ;
     RECT  25.835 9.054 25.871 9.072 ;
     RECT  25.835 17.154 25.871 17.172 ;
     RECT  25.799 26.676 25.871 27.324 ;
     RECT  25.835 16.344 25.907 16.362 ;
     RECT  25.871 26.91 25.907 27.009 ;
     RECT  25.627 32.976 25.907 33.066 ;
     RECT  25.807 40.986 25.907 41.004 ;
    LAYER M3 ;
     RECT  24.228 0.715 24.246 1.291 ;
     RECT  12.348 1.147 12.366 1.723 ;
     RECT  22.896 1.003 22.914 1.867 ;
     RECT  22.896 1.867 23.454 2.011 ;
     RECT  5.652 1.723 5.67 2.143 ;
     RECT  12.348 1.723 12.87 2.143 ;
     RECT  24.228 1.291 24.534 2.155 ;
     RECT  2.415 2.143 2.505 2.413 ;
     RECT  7.815 2.143 7.905 2.413 ;
     RECT  10.515 2.143 10.605 2.413 ;
     RECT  12.348 2.143 13.305 2.413 ;
     RECT  15.915 2.143 16.005 2.413 ;
     RECT  16.884 1.579 16.902 2.413 ;
     RECT  18.615 2.143 18.705 2.413 ;
     RECT  21.315 2.143 21.405 2.413 ;
     RECT  22.212 2.011 23.454 2.413 ;
     RECT  24.192 2.155 24.534 2.443 ;
     RECT  21.315 2.413 23.454 2.827 ;
     RECT  15.915 2.413 16.902 3.307 ;
     RECT  17.784 0.859 17.802 3.307 ;
     RECT  12.348 2.413 13.497 3.547 ;
     RECT  14.688 2.533 14.706 3.547 ;
     RECT  20.772 2.827 23.454 3.595 ;
     RECT  24.192 2.443 24.858 3.595 ;
     RECT  12.348 3.547 13.59 3.677 ;
     RECT  14.688 3.547 14.85 3.677 ;
     RECT  19.8 1.435 19.818 3.835 ;
     RECT  12.348 3.677 13.497 4.123 ;
     RECT  25.74 3.451 25.758 4.157 ;
     RECT  20.772 3.595 24.858 4.459 ;
     RECT  20.7 4.459 24.858 4.496 ;
     RECT  20.772 4.496 24.858 4.747 ;
     RECT  12.096 4.123 13.497 5.179 ;
     RECT  12.096 5.179 13.95 5.755 ;
     RECT  10.515 2.413 10.797 6.331 ;
     RECT  11.808 5.755 13.95 6.331 ;
     RECT  15.915 3.307 17.802 6.547 ;
     RECT  18.615 2.413 18.897 6.547 ;
     RECT  14.688 3.677 14.706 6.619 ;
     RECT  20.772 4.747 25.074 6.619 ;
     RECT  25.812 6.475 25.83 6.619 ;
     RECT  3.528 5.881 3.546 6.691 ;
     RECT  20.772 6.619 25.83 6.845 ;
     RECT  24.192 6.845 25.83 7.079 ;
     RECT  3.528 6.691 3.726 7.231 ;
     RECT  14.688 6.619 14.85 7.393 ;
     RECT  15.915 6.547 18.897 7.393 ;
     RECT  19.692 3.835 19.818 7.393 ;
     RECT  20.772 6.845 23.454 7.393 ;
     RECT  7.815 2.413 8.097 7.699 ;
     RECT  5.115 2.143 5.67 7.735 ;
     RECT  6.588 7.627 6.606 7.735 ;
     RECT  4.968 7.735 6.606 7.771 ;
     RECT  7.344 7.699 8.097 7.771 ;
     RECT  4.968 7.771 8.097 7.889 ;
     RECT  9 7.771 9.162 7.889 ;
     RECT  9 7.889 9.018 7.961 ;
     RECT  19.692 7.393 23.454 8.059 ;
     RECT  24.192 7.079 25.794 8.059 ;
     RECT  19.692 8.059 25.794 8.237 ;
     RECT  2.415 2.413 2.697 8.491 ;
     RECT  2.304 8.491 2.697 8.509 ;
     RECT  3.456 7.231 3.726 8.509 ;
     RECT  2.304 8.509 3.726 8.545 ;
     RECT  2.304 8.545 3.978 8.581 ;
     RECT  5.115 7.889 8.097 8.671 ;
     RECT  2.304 8.581 4.194 8.815 ;
     RECT  5.115 8.671 8.19 8.815 ;
     RECT  2.304 8.815 8.19 8.851 ;
     RECT  2.304 8.851 8.838 8.941 ;
     RECT  25.776 8.237 25.794 9.049 ;
     RECT  2.304 8.941 9.414 9.211 ;
     RECT  2.268 9.211 9.414 9.347 ;
     RECT  2.415 9.347 9.414 9.481 ;
     RECT  25.776 9.049 25.866 9.643 ;
     RECT  19.692 8.237 24.858 9.787 ;
     RECT  25.74 9.643 25.866 9.787 ;
     RECT  2.415 9.481 9.45 9.931 ;
     RECT  19.692 9.787 25.866 10.049 ;
     RECT  2.415 9.931 9.774 10.129 ;
     RECT  10.515 6.331 13.95 10.129 ;
     RECT  0.144 9.547 0.162 10.157 ;
     RECT  19.692 10.049 25.074 10.201 ;
     RECT  2.415 10.129 13.95 10.219 ;
     RECT  2.304 10.219 13.95 10.363 ;
     RECT  14.688 7.393 18.897 10.363 ;
     RECT  19.656 10.201 25.074 10.795 ;
     RECT  25.848 10.049 25.866 10.795 ;
     RECT  2.304 10.363 18.897 11.101 ;
     RECT  19.656 10.795 25.866 11.101 ;
     RECT  2.304 11.101 25.866 11.399 ;
     RECT  2.304 11.399 13.95 12.253 ;
     RECT  14.688 11.399 25.866 12.253 ;
     RECT  0.54 12.217 0.558 12.487 ;
     RECT  0.504 12.487 0.558 12.557 ;
     RECT  0.504 12.557 0.522 12.701 ;
     RECT  0.144 12.859 0.162 13.027 ;
     RECT  0.108 13.027 0.162 13.133 ;
     RECT  0.144 13.133 0.162 13.661 ;
     RECT  2.304 12.253 25.866 14.009 ;
     RECT  0.54 14.215 0.558 14.861 ;
     RECT  2.415 14.009 25.866 14.971 ;
     RECT  2.34 14.971 25.866 15.403 ;
     RECT  0.144 15.019 0.162 15.821 ;
     RECT  2.304 15.403 25.866 16.339 ;
     RECT  0.144 16.891 0.162 17.021 ;
     RECT  0.108 17.077 0.126 17.165 ;
     RECT  0.144 20.347 0.162 20.477 ;
     RECT  0.144 21.499 0.162 21.629 ;
     RECT  2.304 16.339 25.902 21.883 ;
     RECT  2.232 21.883 25.902 22.013 ;
     RECT  0.54 22.621 0.558 24.077 ;
     RECT  2.304 22.013 25.902 25.181 ;
     RECT  2.376 25.181 25.902 25.241 ;
     RECT  0.144 25.339 0.162 25.963 ;
     RECT  2.415 25.241 25.902 25.963 ;
     RECT  0.144 25.963 0.234 26.093 ;
     RECT  0.144 26.093 0.162 26.333 ;
     RECT  0.144 29.659 0.162 30.365 ;
     RECT  2.304 25.963 25.902 31.289 ;
     RECT  0.144 31.387 0.162 31.517 ;
     RECT  2.34 31.289 25.902 32.251 ;
     RECT  2.304 32.251 25.902 34.349 ;
     RECT  0.144 34.843 0.162 34.973 ;
     RECT  2.304 34.349 18.897 35.755 ;
     RECT  2.232 35.755 18.897 35.885 ;
     RECT  19.656 34.349 25.902 36.461 ;
     RECT  0.144 36.811 0.162 37.037 ;
     RECT  24.156 36.461 25.902 38.189 ;
     RECT  0.144 38.203 0.162 38.333 ;
     RECT  2.304 35.885 18.897 38.875 ;
     RECT  2.268 38.875 18.897 38.939 ;
     RECT  19.656 36.461 23.382 39.019 ;
     RECT  24.228 38.189 25.902 39.019 ;
     RECT  19.656 39.019 25.902 39.197 ;
     RECT  25.812 39.197 25.902 39.773 ;
     RECT  0.324 39.883 0.342 40.061 ;
     RECT  2.304 38.939 18.897 40.433 ;
     RECT  19.656 39.197 25.002 40.493 ;
     RECT  0.144 40.459 0.162 40.589 ;
     RECT  25.884 39.773 25.902 40.981 ;
     RECT  2.304 40.433 15.174 41.009 ;
     RECT  25.812 40.981 25.902 41.009 ;
     RECT  25.812 41.009 25.83 41.069 ;
     RECT  19.656 40.493 23.958 41.213 ;
     RECT  25.74 41.227 25.758 41.357 ;
     RECT  20.448 41.213 23.958 41.645 ;
     RECT  20.448 41.645 23.382 42.365 ;
     RECT  24.768 40.493 25.002 42.457 ;
     RECT  2.304 41.009 15.138 42.521 ;
     RECT  0.144 41.611 0.162 42.727 ;
     RECT  0.144 42.727 0.558 42.797 ;
     RECT  23.364 42.365 23.382 42.797 ;
     RECT  24.768 42.457 25.11 42.941 ;
     RECT  19.656 41.213 19.71 43.061 ;
     RECT  25.74 43.099 25.758 43.229 ;
     RECT  0.144 42.797 0.162 43.517 ;
     RECT  20.448 42.365 22.59 43.601 ;
     RECT  2.304 42.521 13.734 44.069 ;
     RECT  10.224 44.069 13.734 44.213 ;
     RECT  2.304 44.069 9.486 44.237 ;
     RECT  24.768 42.941 24.786 44.339 ;
     RECT  0.108 44.491 0.126 44.528 ;
     RECT  20.448 43.601 21.597 44.753 ;
     RECT  12.492 44.213 13.734 44.789 ;
     RECT  10.224 44.213 11.646 44.879 ;
     RECT  0.144 44.779 0.162 44.909 ;
     RECT  10.368 44.879 11.646 45.149 ;
     RECT  20.952 44.753 21.597 45.329 ;
     RECT  2.415 44.237 9.486 45.355 ;
     RECT  10.368 45.149 11.394 45.419 ;
     RECT  14.652 42.521 15.138 45.599 ;
     RECT  15.915 40.433 18.897 45.869 ;
     RECT  12.492 44.789 13.497 45.959 ;
     RECT  17.928 45.869 18.897 46.229 ;
     RECT  14.652 45.599 15.102 46.301 ;
     RECT  10.515 45.419 11.394 46.345 ;
     RECT  2.304 45.355 9.486 46.409 ;
     RECT  18.072 46.229 18.897 46.409 ;
     RECT  2.34 46.409 9.486 46.541 ;
     RECT  2.415 46.541 9.486 47.131 ;
     RECT  10.515 46.345 11.466 47.219 ;
     RECT  10.515 47.219 11.106 47.309 ;
     RECT  2.415 47.131 9.738 47.317 ;
     RECT  10.515 47.309 11.034 47.317 ;
     RECT  2.415 47.317 11.034 47.515 ;
     RECT  22.572 43.601 22.59 47.687 ;
     RECT  15.915 45.869 16.902 47.759 ;
     RECT  19.692 43.061 19.71 48.029 ;
     RECT  0.54 47.857 0.558 48.091 ;
     RECT  0.144 48.091 0.558 48.413 ;
     RECT  2.304 47.515 11.034 48.569 ;
     RECT  14.652 46.301 14.67 48.797 ;
     RECT  0.144 48.413 0.522 48.845 ;
     RECT  0.504 48.845 0.522 48.989 ;
     RECT  2.415 48.569 11.034 49.307 ;
     RECT  7.56 49.307 11.034 49.343 ;
     RECT  7.815 49.343 11.034 49.379 ;
     RECT  7.815 49.379 10.797 49.427 ;
     RECT  13.215 45.959 13.497 49.427 ;
     RECT  15.915 47.759 16.197 49.427 ;
     RECT  18.615 46.409 18.897 49.427 ;
     RECT  21.315 45.329 21.597 49.427 ;
     RECT  2.415 49.307 6.786 49.469 ;
     RECT  7.815 49.427 10.605 49.469 ;
     RECT  2.415 49.469 6.246 49.477 ;
     RECT  2.304 49.477 6.246 49.505 ;
     RECT  2.304 49.505 4.122 49.541 ;
     RECT  2.304 49.541 3.402 49.565 ;
     RECT  7.815 49.469 9.738 49.577 ;
     RECT  5.115 49.505 6.246 49.697 ;
     RECT  7.815 49.577 9.342 49.697 ;
     RECT  10.515 49.469 10.605 49.697 ;
     RECT  13.215 49.427 13.305 49.697 ;
     RECT  15.915 49.427 16.005 49.697 ;
     RECT  18.615 49.427 18.705 49.697 ;
     RECT  21.315 49.427 21.405 49.697 ;
     RECT  0.144 49.579 0.162 49.709 ;
     RECT  8.496 49.697 9.342 49.739 ;
     RECT  8.496 49.739 9.126 49.853 ;
     RECT  5.688 49.697 6.246 50.285 ;
     RECT  8.532 49.853 9.126 50.429 ;
     RECT  2.304 49.565 2.898 50.573 ;
     RECT  2.304 50.573 2.322 50.717 ;
     RECT  6.228 50.285 6.246 50.861 ;
     RECT  9.108 50.429 9.126 51.005 ;
    LAYER M4 ;
     RECT  0.06 8.496 2.408 51 ;
     RECT  2.408 2.148 2.512 51 ;
     RECT  2.512 2.418 2.704 51 ;
     RECT  2.704 8.736 5.108 51 ;
     RECT  5.108 2.148 5.404 51 ;
     RECT  5.461 1.728 5.681 1.752 ;
     RECT  5.404 8.736 5.717 45.24 ;
     RECT  5.317 0.096 5.795 0.12 ;
     RECT  5.717 11.952 6.373 45.24 ;
     RECT  5.404 46.224 6.373 46.872 ;
     RECT  6.373 11.952 6.46 47.064 ;
     RECT  6.46 46.224 6.613 47.064 ;
     RECT  5.404 48.096 6.613 51 ;
     RECT  6.46 33.6 6.689 45.24 ;
     RECT  5.717 8.736 7.808 10.68 ;
     RECT  6.46 11.952 7.808 32.568 ;
     RECT  6.689 33.6 7.808 41.784 ;
     RECT  6.689 42.768 7.808 45.24 ;
     RECT  6.613 46.224 7.808 51 ;
     RECT  7.808 2.148 7.912 51 ;
     RECT  7.912 2.418 8.104 51 ;
     RECT  8.104 12.528 8.165 13.704 ;
     RECT  8.104 34.896 8.165 37.176 ;
     RECT  8.104 9.024 8.243 10.968 ;
     RECT  8.104 14.736 8.243 19.608 ;
     RECT  8.104 23.04 8.243 26.76 ;
     RECT  8.165 34.896 8.243 36.024 ;
     RECT  8.104 46.08 8.243 51 ;
     RECT  8.165 12.768 8.245 13.704 ;
     RECT  8.243 14.736 8.245 18.744 ;
     RECT  8.243 34.896 8.273 35.304 ;
     RECT  8.245 14.736 8.291 18.168 ;
     RECT  8.104 29.616 8.309 31.992 ;
     RECT  8.104 41.28 8.381 44.088 ;
     RECT  8.243 23.04 8.489 24.504 ;
     RECT  8.245 12.768 8.525 12.888 ;
     RECT  8.291 15.984 8.525 18.168 ;
     RECT  8.309 31.968 8.525 31.992 ;
     RECT  8.381 41.28 8.531 43.704 ;
     RECT  8.243 46.752 8.561 51 ;
     RECT  8.273 34.944 8.597 35.304 ;
     RECT  8.531 41.76 8.597 41.784 ;
     RECT  8.104 33.264 8.633 33.912 ;
     RECT  8.531 42.816 8.741 43.704 ;
     RECT  8.104 38.16 8.813 39.336 ;
     RECT  8.525 15.984 8.849 16.392 ;
     RECT  8.291 14.784 8.957 14.808 ;
     RECT  8.849 16.272 8.957 16.392 ;
     RECT  8.741 43.68 8.957 43.704 ;
     RECT  8.957 16.32 9.101 16.392 ;
     RECT  8.525 17.808 9.101 18.024 ;
     RECT  8.525 12.768 9.137 12.792 ;
     RECT  8.561 50.976 9.137 51 ;
     RECT  8.243 25.776 9.205 26.76 ;
     RECT  9.101 16.368 9.209 16.392 ;
     RECT  9.205 25.104 9.209 26.76 ;
     RECT  8.243 9.84 9.245 9.864 ;
     RECT  8.489 23.04 9.245 23.64 ;
     RECT  8.104 27.936 9.277 28.488 ;
     RECT  8.309 29.616 9.277 30.696 ;
     RECT  9.277 27.936 9.353 30.696 ;
     RECT  8.597 34.944 9.353 35.064 ;
     RECT  9.353 27.936 9.389 29.112 ;
     RECT  8.561 46.752 9.389 49.512 ;
     RECT  9.209 25.104 9.425 26.376 ;
     RECT  9.389 27.936 9.457 28.248 ;
     RECT  9.457 27.408 9.461 28.248 ;
     RECT  9.205 33.168 9.461 33.192 ;
     RECT  9.353 30.192 9.497 30.696 ;
     RECT  8.104 21.792 10.321 22.056 ;
     RECT  9.245 23.136 10.321 23.64 ;
     RECT  9.853 13.104 10.508 13.128 ;
     RECT  9.101 17.808 10.508 17.832 ;
     RECT  10.321 21.408 10.508 22.056 ;
     RECT  10.321 23.136 10.508 23.88 ;
     RECT  9.425 25.104 10.508 25.224 ;
     RECT  9.461 27.408 10.508 27.96 ;
     RECT  9.497 30.384 10.508 30.696 ;
     RECT  9.349 31.776 10.508 31.8 ;
     RECT  9.385 34.656 10.508 34.68 ;
     RECT  8.813 38.736 10.508 39.336 ;
     RECT  9.389 47.136 10.508 49.512 ;
     RECT  10.508 2.148 10.612 49.692 ;
     RECT  10.612 2.418 10.804 49.422 ;
     RECT  10.804 23.616 10.865 24.216 ;
     RECT  10.804 48.768 10.901 48.936 ;
     RECT  10.804 22.512 10.973 22.536 ;
     RECT  10.804 17.616 11.081 17.64 ;
     RECT  10.865 23.616 11.081 23.88 ;
     RECT  11.081 23.616 11.225 23.64 ;
     RECT  10.804 21.408 11.261 21.432 ;
     RECT  10.804 29.088 11.333 29.112 ;
     RECT  10.804 6.336 11.797 6.36 ;
     RECT  10.804 36.288 12.265 36.312 ;
     RECT  10.804 37.44 12.265 37.464 ;
     RECT  12.265 25.104 12.625 25.128 ;
     RECT  12.337 1.152 12.841 1.176 ;
     RECT  12.085 4.128 12.877 4.152 ;
     RECT  11.905 41.472 12.877 41.496 ;
     RECT  12.985 28.8 13.165 28.824 ;
     RECT  12.841 1.152 13.208 1.752 ;
     RECT  12.877 3.648 13.208 4.152 ;
     RECT  11.797 5.76 13.208 6.36 ;
     RECT  12.121 19.104 13.208 19.128 ;
     RECT  12.121 22.848 13.208 22.872 ;
     RECT  12.625 25.104 13.208 25.176 ;
     RECT  13.165 28.8 13.208 29.016 ;
     RECT  10.804 34.992 13.208 35.016 ;
     RECT  12.265 36.288 13.208 37.464 ;
     RECT  10.804 38.736 13.208 39.336 ;
     RECT  12.193 40.32 13.208 40.344 ;
     RECT  12.877 41.472 13.208 41.928 ;
     RECT  10.804 43.104 13.208 43.128 ;
     RECT  10.901 48.768 13.208 48.792 ;
     RECT  13.208 1.152 13.312 49.692 ;
     RECT  13.312 1.152 13.504 49.422 ;
     RECT  13.504 26.256 14.249 26.52 ;
     RECT  14.249 26.496 14.497 26.52 ;
     RECT  13.504 30.816 14.497 30.84 ;
     RECT  14.497 26.496 14.605 26.808 ;
     RECT  14.605 26.496 14.609 27.672 ;
     RECT  14.497 30.816 14.609 30.936 ;
     RECT  13.504 48.768 14.681 48.792 ;
     RECT  14.609 26.496 14.717 26.52 ;
     RECT  13.504 35.136 14.821 35.16 ;
     RECT  14.609 27.648 14.825 27.672 ;
     RECT  14.609 30.912 14.825 30.936 ;
     RECT  13.504 3.552 14.861 4.152 ;
     RECT  14.821 35.136 14.861 35.256 ;
     RECT  14.861 35.232 15.397 35.256 ;
     RECT  13.504 36.288 15.397 37.464 ;
     RECT  13.504 15.984 15.829 16.008 ;
     RECT  13.504 1.152 15.908 1.752 ;
     RECT  14.861 3.648 15.908 4.152 ;
     RECT  13.504 5.184 15.908 6.36 ;
     RECT  13.504 10.368 15.908 10.392 ;
     RECT  15.829 15.264 15.908 16.008 ;
     RECT  15.289 23.904 15.908 23.928 ;
     RECT  13.504 28.8 15.908 28.824 ;
     RECT  15.397 35.232 15.908 37.464 ;
     RECT  13.504 38.736 15.908 39.336 ;
     RECT  13.504 40.32 15.908 43.128 ;
     RECT  15.908 1.152 16.012 49.692 ;
     RECT  16.012 1.152 16.204 49.422 ;
     RECT  16.204 18.768 16.337 18.792 ;
     RECT  16.204 23.28 16.985 23.304 ;
     RECT  16.204 21.984 17.093 22.008 ;
     RECT  16.204 3.648 17.233 6.936 ;
     RECT  16.204 28.8 17.485 28.824 ;
     RECT  17.485 28.224 17.701 28.824 ;
     RECT  16.204 1.152 17.773 1.752 ;
     RECT  17.197 14.112 17.809 14.136 ;
     RECT  16.204 15.264 17.809 16.008 ;
     RECT  16.204 26.352 17.881 26.376 ;
     RECT  16.204 10.368 18.133 10.392 ;
     RECT  17.809 14.112 18.169 16.008 ;
     RECT  17.773 0.864 18.608 1.752 ;
     RECT  17.233 3.312 18.608 6.936 ;
     RECT  18.133 10.368 18.608 10.968 ;
     RECT  18.169 13.824 18.608 16.008 ;
     RECT  18.529 18.816 18.608 18.84 ;
     RECT  17.881 26.352 18.608 26.568 ;
     RECT  17.701 28.08 18.608 28.824 ;
     RECT  16.204 35.232 18.608 37.464 ;
     RECT  16.204 38.736 18.608 43.128 ;
     RECT  18.608 0.864 18.712 49.692 ;
     RECT  18.712 0.864 18.904 49.422 ;
     RECT  18.904 19.056 19.037 19.08 ;
     RECT  18.904 21.216 19.289 21.24 ;
     RECT  18.904 26.304 19.897 26.52 ;
     RECT  19.897 26.304 20.149 27.384 ;
     RECT  18.904 13.824 20.401 16.392 ;
     RECT  18.904 28.512 20.509 29.784 ;
     RECT  18.904 31.104 20.509 31.416 ;
     RECT  20.149 25.536 20.725 27.384 ;
     RECT  20.509 28.512 20.725 31.416 ;
     RECT  18.904 3.408 20.761 6.936 ;
     RECT  18.904 10.368 20.941 11.544 ;
     RECT  18.904 35.136 21.013 37.464 ;
     RECT  18.904 0.864 21.308 1.752 ;
     RECT  20.761 2.832 21.308 6.936 ;
     RECT  19.933 8.784 21.308 8.808 ;
     RECT  20.941 10.08 21.308 11.544 ;
     RECT  20.401 13.68 21.308 16.392 ;
     RECT  18.904 22.464 21.308 22.488 ;
     RECT  20.725 25.536 21.308 31.416 ;
     RECT  18.904 32.832 21.308 32.856 ;
     RECT  21.013 34.992 21.308 37.464 ;
     RECT  18.904 38.736 21.308 43.128 ;
     RECT  21.308 0.864 21.412 49.692 ;
     RECT  21.412 0.864 21.604 49.422 ;
     RECT  21.604 26.736 22.241 31.416 ;
     RECT  21.604 25.344 22.633 25.368 ;
     RECT  21.604 21.888 22.705 22.488 ;
     RECT  21.604 8.784 22.777 11.832 ;
     RECT  21.604 12.96 22.777 18.84 ;
     RECT  21.604 20.016 22.777 20.184 ;
     RECT  22.705 21.888 22.777 22.92 ;
     RECT  22.633 24.768 22.777 25.368 ;
     RECT  21.604 0.864 22.813 7.368 ;
     RECT  22.777 8.352 22.813 11.832 ;
     RECT  22.241 26.784 22.813 31.416 ;
     RECT  21.604 32.832 22.813 33 ;
     RECT  21.604 34.128 22.813 43.128 ;
     RECT  22.777 12.96 23.785 25.656 ;
     RECT  23.785 12.816 24.073 25.656 ;
     RECT  22.813 26.784 24.073 43.128 ;
     RECT  22.813 0.864 24.217 11.832 ;
     RECT  24.217 0.72 24.721 11.832 ;
     RECT  24.073 12.816 24.721 43.128 ;
     RECT  24.721 0.72 25.729 43.128 ;
     RECT  25.729 0.72 25.884 43.224 ;
    LAYER M5 ;
     RECT  5.328 0.016 5.496 0.085 ;
     RECT  5.328 0.085 5.784 0.131 ;
     RECT  5.472 0.131 5.784 2.137 ;
     RECT  2.4 2.137 2.52 2.151 ;
     RECT  7.8 2.137 7.92 2.151 ;
     RECT  10.5 2.137 10.62 2.151 ;
     RECT  13.2 2.137 13.32 2.151 ;
     RECT  15.9 2.137 16.02 2.151 ;
     RECT  18.6 2.137 18.72 2.151 ;
     RECT  21.3 2.137 21.42 2.151 ;
     RECT  7.8 2.151 8.112 9.013 ;
     RECT  2.4 2.151 2.712 10.165 ;
     RECT  7.8 9.013 8.232 10.979 ;
     RECT  2.4 10.165 3.288 12.325 ;
     RECT  2.304 12.325 3.288 12.515 ;
     RECT  2.4 12.515 3.288 12.611 ;
     RECT  7.8 10.979 8.112 12.757 ;
     RECT  7.8 12.757 8.232 13.715 ;
     RECT  5.1 2.137 5.784 14.197 ;
     RECT  2.4 12.611 2.712 14.485 ;
     RECT  2.208 14.485 2.712 14.723 ;
     RECT  7.8 13.715 8.112 14.725 ;
     RECT  2.4 14.723 2.712 15.349 ;
     RECT  5.1 14.197 6.312 15.491 ;
     RECT  5.1 15.491 5.784 16.405 ;
     RECT  2.4 15.349 3.432 16.547 ;
     RECT  7.8 14.725 8.28 16.595 ;
     RECT  4.56 16.405 5.784 17.317 ;
     RECT  4.56 17.317 6.552 17.461 ;
     RECT  7.8 16.595 8.112 17.461 ;
     RECT  4.56 17.461 8.112 17.651 ;
     RECT  4.56 17.651 6.552 17.699 ;
     RECT  2.4 16.547 2.712 18.517 ;
     RECT  2.304 18.517 2.712 18.707 ;
     RECT  7.8 17.651 8.112 18.709 ;
     RECT  2.4 18.707 2.712 18.757 ;
     RECT  7.8 18.709 8.232 19.619 ;
     RECT  2.4 18.757 3.24 20.965 ;
     RECT  2.304 20.965 3.24 21.155 ;
     RECT  5.1 17.699 6.552 22.549 ;
     RECT  4.848 22.549 6.552 23.125 ;
     RECT  2.4 21.155 3.24 23.315 ;
     RECT  4.8 23.125 6.552 23.603 ;
     RECT  7.8 19.619 8.112 23.893 ;
     RECT  4.848 23.603 6.552 23.987 ;
     RECT  4.992 23.987 6.552 24.035 ;
     RECT  7.8 23.893 8.232 24.469 ;
     RECT  5.1 24.035 6.552 24.611 ;
     RECT  2.4 23.315 2.712 24.997 ;
     RECT  10.5 2.151 10.812 25.093 ;
     RECT  2.304 24.997 2.712 25.187 ;
     RECT  9.552 25.093 10.812 25.235 ;
     RECT  7.8 24.469 8.328 27.971 ;
     RECT  5.1 24.611 5.976 28.261 ;
     RECT  4.992 28.261 5.976 29.509 ;
     RECT  4.992 29.509 6.408 29.699 ;
     RECT  5.1 29.699 6.408 30.229 ;
     RECT  7.8 27.971 8.112 30.229 ;
     RECT  9.168 29.893 9.192 30.323 ;
     RECT  5.1 30.229 8.112 30.419 ;
     RECT  5.1 30.419 6.408 30.899 ;
     RECT  2.4 25.187 2.712 31.717 ;
     RECT  2.208 31.717 2.712 31.859 ;
     RECT  5.1 30.899 5.88 32.437 ;
     RECT  7.8 30.419 8.112 34.933 ;
     RECT  5.1 32.437 6.408 35.411 ;
     RECT  7.8 34.933 8.232 36.035 ;
     RECT  5.1 35.411 5.688 37.333 ;
     RECT  3.936 34.741 3.96 37.379 ;
     RECT  2.4 31.859 2.712 39.829 ;
     RECT  0.144 40.021 0.168 40.163 ;
     RECT  7.8 36.035 8.112 41.269 ;
     RECT  7.8 41.269 8.52 42.851 ;
     RECT  2.4 39.829 3.288 43.043 ;
     RECT  5.1 37.333 6.168 44.387 ;
     RECT  5.1 44.387 5.736 45.541 ;
     RECT  7.8 42.851 8.112 46.069 ;
     RECT  5.1 45.541 6.408 46.307 ;
     RECT  7.8 46.069 8.232 46.741 ;
     RECT  2.4 43.043 2.712 46.837 ;
     RECT  7.392 46.741 8.232 46.931 ;
     RECT  2.304 46.837 2.712 46.979 ;
     RECT  6.384 46.307 6.408 47.075 ;
     RECT  7.8 46.931 8.232 47.891 ;
     RECT  2.4 46.979 2.712 49.093 ;
     RECT  2.304 49.093 2.712 49.235 ;
     RECT  2.4 49.235 2.712 49.689 ;
     RECT  5.1 46.307 5.412 49.689 ;
     RECT  7.8 47.891 8.112 49.689 ;
     RECT  10.5 25.235 10.812 49.689 ;
     RECT  13.2 2.151 13.512 49.689 ;
     RECT  15.9 2.151 16.212 49.689 ;
     RECT  18.6 2.151 18.912 49.689 ;
     RECT  21.3 2.151 21.612 49.689 ;
     RECT  2.4 49.689 2.52 49.703 ;
     RECT  5.1 49.689 5.22 49.703 ;
     RECT  7.8 49.689 7.92 49.703 ;
     RECT  10.5 49.689 10.62 49.703 ;
     RECT  13.2 49.689 13.32 49.703 ;
     RECT  15.9 49.689 16.02 49.703 ;
     RECT  18.6 49.689 18.72 49.703 ;
     RECT  21.3 49.689 21.42 49.703 ;
  END
END qkd_astk_rly_296
END LIBRARY
